# Generated by innovus_enablement/scripts/gen_innovus_lef.py from ../i3dPDK_NS3K/BE/i3dPDK_NS3K_5T_0V7_27C.lef
# Read AFTER the matching i3dPDK_NS3K_<N>T_tech.lef.
VERSION 5.8 ;
BUSBITCHARS "[]" ;
DIVIDERCHAR "/" ;





























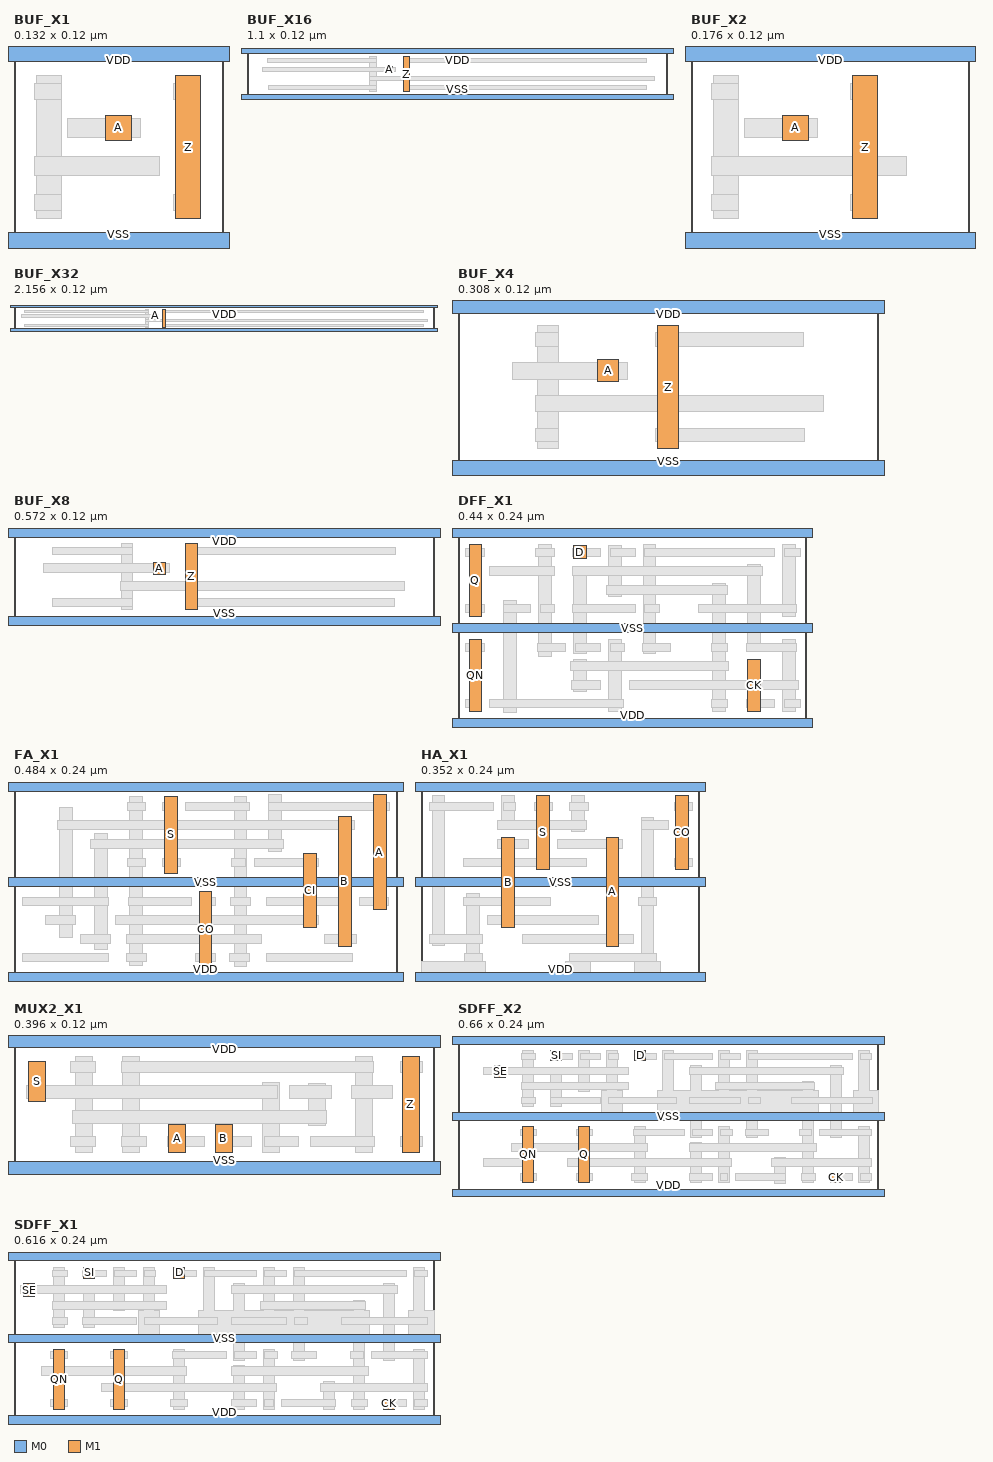
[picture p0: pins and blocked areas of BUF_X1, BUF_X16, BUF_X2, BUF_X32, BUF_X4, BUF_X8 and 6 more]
MACRO BUF_X1
  CLASS CORE ;
  ORIGIN 0 0 ;
  FOREIGN BUF_X1 0 0 ;
  SYMMETRY X Y ;
  SITE i3d_nsfet3nm ;
  SIZE 0.132 BY 0.12 ;
  PIN VDD
    DIRECTION INOUT ;
    USE POWER ;
    PORT
      LAYER M0 ;
        RECT -0.0160 0.1140 0.1480 0.1260 ;
    END
  END VDD
  PIN VSS
    DIRECTION INOUT ;
    USE GROUND ;
    PORT
      LAYER M0 ;
        RECT -0.0160 -0.0060 0.1480 0.0060 ;
    END
  END VSS
  PIN A
    DIRECTION INPUT ;
    USE SIGNAL ;
    PORT
      LAYER M1 ;
        RECT 0.0580 0.0640 0.0740 0.0800 ;
    END
  END A
  PIN Z
    DIRECTION OUTPUT ;
    USE SIGNAL ;
    PORT
      LAYER M1 ;
        RECT 0.1020 0.0150 0.1180 0.1050 ;
    END
  END Z
  OBS
    LAYER M1 DESIGNRULEWIDTH 0 ;
      RECT 0.0140 0.0150 0.0300 0.1050 ;
    LAYER M0 DESIGNRULEWIDTH 0 ;
      RECT 0.1010 0.0200 0.1180 0.0300 ;
      RECT 0.0130 0.0200 0.0300 0.0300 ;
      RECT 0.0130 0.0420 0.0920 0.0540 ;
      RECT 0.0340 0.0660 0.0800 0.0780 ;
      RECT 0.1010 0.0900 0.1180 0.1000 ;
      RECT 0.0130 0.0900 0.0300 0.1000 ;
  END
END BUF_X1

MACRO BUF_X16
  CLASS CORE ;
  ORIGIN 0 0 ;
  FOREIGN BUF_X16 0 0 ;
  SYMMETRY X Y ;
  SITE i3d_nsfet3nm ;
  SIZE 1.1 BY 0.12 ;
  PIN VDD
    DIRECTION INOUT ;
    USE POWER ;
    PORT
      LAYER M0 ;
        RECT -0.0160 0.1140 1.1160 0.1260 ;
    END
  END VDD
  PIN VSS
    DIRECTION INOUT ;
    USE GROUND ;
    PORT
      LAYER M0 ;
        RECT -0.0160 -0.0060 1.1160 0.0060 ;
    END
  END VSS
  PIN A
    DIRECTION INPUT ;
    USE SIGNAL ;
    PORT
      LAYER M1 ;
        RECT 0.3660 0.0640 0.3820 0.0800 ;
    END
  END A
  PIN Z
    DIRECTION OUTPUT ;
    USE SIGNAL ;
    PORT
      LAYER M1 ;
        RECT 0.4100 0.0150 0.4260 0.1050 ;
    END
  END Z
  OBS
    LAYER M1 DESIGNRULEWIDTH 0 ;
      RECT 0.3220 0.0150 0.3380 0.1050 ;
    LAYER M0 DESIGNRULEWIDTH 0 ;
      RECT 0.4090 0.0200 1.0460 0.0300 ;
      RECT 0.0560 0.0200 0.3380 0.0300 ;
      RECT 0.3210 0.0420 1.0660 0.0540 ;
      RECT 0.0400 0.0660 0.3880 0.0780 ;
      RECT 0.4090 0.0900 1.0470 0.1000 ;
      RECT 0.0530 0.0900 0.3380 0.1000 ;
  END
END BUF_X16

MACRO BUF_X2
  CLASS CORE ;
  ORIGIN 0 0 ;
  FOREIGN BUF_X2 0 0 ;
  SYMMETRY X Y ;
  SITE i3d_nsfet3nm ;
  SIZE 0.176 BY 0.12 ;
  PIN VDD
    DIRECTION INOUT ;
    USE POWER ;
    PORT
      LAYER M0 ;
        RECT -0.0160 0.1140 0.1920 0.1260 ;
    END
  END VDD
  PIN VSS
    DIRECTION INOUT ;
    USE GROUND ;
    PORT
      LAYER M0 ;
        RECT -0.0160 -0.0060 0.1920 0.0060 ;
    END
  END VSS
  PIN A
    DIRECTION INPUT ;
    USE SIGNAL ;
    PORT
      LAYER M1 ;
        RECT 0.0580 0.0640 0.0740 0.0800 ;
    END
  END A
  PIN Z
    DIRECTION OUTPUT ;
    USE SIGNAL ;
    PORT
      LAYER M1 ;
        RECT 0.1020 0.0150 0.1180 0.1050 ;
    END
  END Z
  OBS
    LAYER M1 DESIGNRULEWIDTH 0 ;
      RECT 0.0140 0.0150 0.0300 0.1050 ;
    LAYER M0 DESIGNRULEWIDTH 0 ;
      RECT 0.1010 0.0200 0.1180 0.0300 ;
      RECT 0.0130 0.0200 0.0300 0.0300 ;
      RECT 0.0130 0.0420 0.1360 0.0540 ;
      RECT 0.0340 0.0660 0.0800 0.0780 ;
      RECT 0.1010 0.0900 0.1180 0.1000 ;
      RECT 0.0130 0.0900 0.0300 0.1000 ;
  END
END BUF_X2

MACRO BUF_X32
  CLASS CORE ;
  ORIGIN 0 0 ;
  FOREIGN BUF_X32 0 0 ;
  SYMMETRY X Y ;
  SITE i3d_nsfet3nm ;
  SIZE 2.156 BY 0.12 ;
  PIN VDD
    DIRECTION INOUT ;
    USE POWER ;
    PORT
      LAYER M0 ;
        RECT -0.0160 0.1140 2.1720 0.1260 ;
    END
  END VDD
  PIN VSS
    DIRECTION INOUT ;
    USE GROUND ;
    PORT
      LAYER M0 ;
        RECT -0.0160 -0.0060 2.1720 0.0060 ;
    END
  END VSS
  PIN Z
    DIRECTION OUTPUT ;
    USE SIGNAL ;
    PORT
      LAYER M1 ;
        RECT 0.7620 0.0150 0.7780 0.1050 ;
    END
  END Z
  PIN A
    DIRECTION INPUT ;
    USE SIGNAL ;
    PORT
      LAYER M1 ;
        RECT 0.7180 0.0640 0.7340 0.0800 ;
    END
  END A
  OBS
    LAYER M1 DESIGNRULEWIDTH 0 ;
      RECT 0.6740 0.0150 0.6900 0.1050 ;
    LAYER M0 DESIGNRULEWIDTH 0 ;
      RECT 0.7610 0.0200 2.1040 0.0300 ;
      RECT 0.0550 0.0200 0.6900 0.0300 ;
      RECT 0.6730 0.0420 2.1230 0.0540 ;
      RECT 0.0390 0.0660 0.7400 0.0780 ;
      RECT 0.7610 0.0900 2.1010 0.1000 ;
      RECT 0.0530 0.0900 0.6900 0.1000 ;
  END
END BUF_X32

MACRO BUF_X4
  CLASS CORE ;
  ORIGIN 0 0 ;
  FOREIGN BUF_X4 0 0 ;
  SYMMETRY X Y ;
  SITE i3d_nsfet3nm ;
  SIZE 0.308 BY 0.12 ;
  PIN VDD
    DIRECTION INOUT ;
    USE POWER ;
    PORT
      LAYER M0 ;
        RECT -0.0160 0.1140 0.3240 0.1260 ;
    END
  END VDD
  PIN VSS
    DIRECTION INOUT ;
    USE GROUND ;
    PORT
      LAYER M0 ;
        RECT -0.0160 -0.0060 0.3240 0.0060 ;
    END
  END VSS
  PIN A
    DIRECTION INPUT ;
    USE SIGNAL ;
    PORT
      LAYER M1 ;
        RECT 0.1020 0.0640 0.1180 0.0800 ;
    END
  END A
  PIN Z
    DIRECTION OUTPUT ;
    USE SIGNAL ;
    PORT
      LAYER M1 ;
        RECT 0.1460 0.0150 0.1620 0.1050 ;
    END
  END Z
  OBS
    LAYER M1 DESIGNRULEWIDTH 0 ;
      RECT 0.0580 0.0150 0.0740 0.1050 ;
    LAYER M0 DESIGNRULEWIDTH 0 ;
      RECT 0.1450 0.0200 0.2540 0.0300 ;
      RECT 0.0570 0.0200 0.0740 0.0300 ;
      RECT 0.0570 0.0420 0.2680 0.0540 ;
      RECT 0.0400 0.0660 0.1240 0.0780 ;
      RECT 0.1450 0.0900 0.2530 0.1000 ;
      RECT 0.0570 0.0900 0.0740 0.1000 ;
  END
END BUF_X4

MACRO BUF_X8
  CLASS CORE ;
  ORIGIN 0 0 ;
  FOREIGN BUF_X8 0 0 ;
  SYMMETRY X Y ;
  SITE i3d_nsfet3nm ;
  SIZE 0.572 BY 0.12 ;
  PIN VDD
    DIRECTION INOUT ;
    USE POWER ;
    PORT
      LAYER M0 ;
        RECT -0.0160 0.1140 0.5880 0.1260 ;
    END
  END VDD
  PIN VSS
    DIRECTION INOUT ;
    USE GROUND ;
    PORT
      LAYER M0 ;
        RECT -0.0160 -0.0060 0.5880 0.0060 ;
    END
  END VSS
  PIN A
    DIRECTION INPUT ;
    USE SIGNAL ;
    PORT
      LAYER M1 ;
        RECT 0.1900 0.0640 0.2060 0.0800 ;
    END
  END A
  PIN Z
    DIRECTION OUTPUT ;
    USE SIGNAL ;
    PORT
      LAYER M1 ;
        RECT 0.2340 0.0150 0.2500 0.1050 ;
    END
  END Z
  OBS
    LAYER M1 DESIGNRULEWIDTH 0 ;
      RECT 0.1460 0.0150 0.1620 0.1050 ;
    LAYER M0 DESIGNRULEWIDTH 0 ;
      RECT 0.2330 0.0200 0.5180 0.0300 ;
      RECT 0.0520 0.0200 0.1620 0.0300 ;
      RECT 0.1450 0.0420 0.5320 0.0540 ;
      RECT 0.0400 0.0660 0.2120 0.0780 ;
      RECT 0.2330 0.0900 0.5190 0.1000 ;
      RECT 0.0520 0.0900 0.1620 0.1000 ;
  END
END BUF_X8

MACRO DFF_X1
  CLASS CORE ;
  ORIGIN 0 0 ;
  FOREIGN DFF_X1 0 0 ;
  SYMMETRY X Y ;
  SITE i3d_nsfet3nm_2H_VDD ;
  SIZE 0.44 BY 0.24 ;
  PIN Q
    DIRECTION OUTPUT ;
    USE SIGNAL ;
    PORT
      LAYER M1 ;
        RECT 0.0140 0.1350 0.0300 0.2250 ;
    END
  END Q
  PIN VDD
    DIRECTION INOUT ;
    USE POWER ;
    PORT
      LAYER M0 ;
        RECT -0.0160 0.2340 0.4560 0.2460 ;
        RECT -0.0160 -0.0060 0.4560 0.0060 ;
    END
  END VDD
  PIN VSS
    DIRECTION INOUT ;
    USE GROUND ;
    PORT
      LAYER M0 ;
        RECT -0.0160 0.1140 0.4560 0.1260 ;
    END
  END VSS
  PIN D
    DIRECTION INPUT ;
    USE SIGNAL ;
    PORT
      LAYER M1 ;
        RECT 0.1460 0.2080 0.1620 0.2240 ;
    END
  END D
  PIN QN
    DIRECTION OUTPUT ;
    USE SIGNAL ;
    PORT
      LAYER M1 ;
        RECT 0.0140 0.0150 0.0300 0.1050 ;
    END
  END QN
  PIN CK
    DIRECTION INPUT ;
    USE SIGNAL ;
    PORT
      LAYER M1 ;
        RECT 0.3660 0.0150 0.3820 0.0800 ;
    END
  END CK
  OBS
    LAYER M1 ;
      RECT 0.0580 0.0130 0.0740 0.1550 ;
      RECT 0.1900 0.0150 0.2060 0.1050 ;
      RECT 0.3220 0.0150 0.3380 0.1760 ;
      RECT 0.4100 0.0150 0.4260 0.1050 ;
      RECT 0.1460 0.0400 0.1620 0.0800 ;
      RECT 0.1020 0.0840 0.1180 0.2250 ;
      RECT 0.1460 0.0880 0.1620 0.1880 ;
      RECT 0.2340 0.0880 0.2500 0.2250 ;
      RECT 0.3660 0.1000 0.3820 0.2000 ;
      RECT 0.4100 0.1350 0.4260 0.2250 ;
      RECT 0.1900 0.1600 0.2060 0.2240 ;
    LAYER M0 ;
      RECT 0.0100 0.0200 0.0280 0.0300 ;
      RECT 0.0400 0.0200 0.2090 0.0300 ;
      RECT 0.3200 0.0200 0.3400 0.0300 ;
      RECT 0.3650 0.0200 0.4000 0.0300 ;
      RECT 0.4120 0.0200 0.4320 0.0300 ;
      RECT 0.1430 0.0420 0.1800 0.0540 ;
      RECT 0.2160 0.0420 0.4300 0.0540 ;
      RECT 0.1420 0.0660 0.3420 0.0780 ;
      RECT 0.0100 0.0900 0.0340 0.1000 ;
      RECT 0.1000 0.0900 0.1360 0.1000 ;
      RECT 0.1480 0.0900 0.1800 0.1000 ;
      RECT 0.1920 0.0900 0.2100 0.1000 ;
      RECT 0.2330 0.0900 0.2680 0.1000 ;
      RECT 0.3200 0.0900 0.3400 0.1000 ;
      RECT 0.3640 0.0900 0.4280 0.1000 ;
      RECT 0.0100 0.1400 0.0340 0.1500 ;
      RECT 0.0570 0.1400 0.0920 0.1500 ;
      RECT 0.1040 0.1400 0.1220 0.1500 ;
      RECT 0.1440 0.1400 0.2240 0.1500 ;
      RECT 0.2360 0.1400 0.2550 0.1500 ;
      RECT 0.3040 0.1400 0.4280 0.1500 ;
      RECT 0.1870 0.1620 0.3400 0.1740 ;
      RECT 0.0400 0.1860 0.1220 0.1980 ;
      RECT 0.1450 0.1860 0.3840 0.1980 ;
      RECT 0.0100 0.2100 0.0340 0.2200 ;
      RECT 0.0980 0.2100 0.1220 0.2200 ;
      RECT 0.1440 0.2100 0.1800 0.2200 ;
      RECT 0.1920 0.2100 0.2240 0.2200 ;
      RECT 0.2360 0.2100 0.4000 0.2200 ;
      RECT 0.4120 0.2100 0.4320 0.2200 ;
  END
END DFF_X1


MACRO FA_X1
  CLASS CORE ;
  ORIGIN 0 0 ;
  FOREIGN FA 0 0 ;
  SYMMETRY X Y ;
  SITE i3d_nsfet3nm_2H_VDD ;
  SIZE 0.484 BY 0.24 ;
  PIN VDD
    DIRECTION INOUT ;
    USE POWER ;
    PORT
      LAYER M0 ;
        RECT -0.0160 -0.0060 0.5000 0.0060 ;
        RECT -0.0160 0.2340 0.5000 0.2460 ;
    END
  END VDD
  PIN VSS
    DIRECTION INOUT ;
    USE GROUND ;
    PORT
      LAYER M0 ;
        RECT -0.0160 0.1140 0.5000 0.1260 ;
    END
  END VSS
  PIN CO
    DIRECTION OUTPUT ;
    USE SIGNAL ;
    PORT
      LAYER M1 ;
        RECT 0.2340 0.0130 0.2500 0.1080 ;
    END
  END CO
  PIN CI
    DIRECTION INPUT ;
    USE SIGNAL ;
    PORT
      LAYER M1 ;
        RECT 0.3660 0.0630 0.3820 0.1560 ;
    END
  END CI
  PIN A
    DIRECTION INPUT ;
    USE SIGNAL ;
    PORT
      LAYER M1 ;
        RECT 0.4540 0.0850 0.4700 0.2300 ;
    END
  END A
  PIN B
    DIRECTION INPUT ;
    USE SIGNAL ;
    PORT
      LAYER M1 ;
        RECT 0.4100 0.0390 0.4260 0.2030 ;
    END
  END B
  PIN S
    DIRECTION OUTPUT ;
    USE SIGNAL ;
    PORT
      LAYER M1 ;
        RECT 0.1900 0.1310 0.2060 0.2280 ;
    END
  END S
  OBS
    LAYER M1 DESIGNRULEWIDTH 0 ;
      RECT 0.2780 0.0130 0.2940 0.2280 ;
      RECT 0.1460 0.0140 0.1620 0.2280 ;
      RECT 0.1020 0.0350 0.1180 0.1810 ;
      RECT 0.0580 0.0500 0.0740 0.2140 ;
      RECT 0.3220 0.1590 0.3380 0.2300 ;
    LAYER M0 DESIGNRULEWIDTH 0 ;
      RECT 0.3190 0.0200 0.4270 0.0300 ;
      RECT 0.2720 0.0200 0.2970 0.0300 ;
      RECT 0.2290 0.0200 0.2540 0.0300 ;
      RECT 0.1420 0.0200 0.1670 0.0300 ;
      RECT 0.0110 0.0200 0.1190 0.0300 ;
      RECT 0.3920 0.0420 0.4320 0.0540 ;
      RECT 0.1420 0.0420 0.3120 0.0540 ;
      RECT 0.0840 0.0420 0.1220 0.0540 ;
      RECT 0.1280 0.0660 0.3840 0.0780 ;
      RECT 0.0400 0.0660 0.0780 0.0780 ;
      RECT 0.4360 0.0900 0.4730 0.1000 ;
      RECT 0.3190 0.0900 0.4240 0.1000 ;
      RECT 0.2740 0.0900 0.2990 0.1000 ;
      RECT 0.2360 0.0900 0.2540 0.1000 ;
      RECT 0.1440 0.0900 0.2240 0.1000 ;
      RECT 0.0110 0.0900 0.1190 0.1000 ;
      RECT 0.3040 0.1400 0.3840 0.1500 ;
      RECT 0.2750 0.1400 0.2920 0.1500 ;
      RECT 0.1870 0.1400 0.2100 0.1500 ;
      RECT 0.1430 0.1400 0.1660 0.1500 ;
      RECT 0.0970 0.1620 0.3400 0.1740 ;
      RECT 0.0550 0.1860 0.4300 0.1980 ;
      RECT 0.3210 0.2100 0.4740 0.2200 ;
      RECT 0.2160 0.2100 0.2980 0.2200 ;
      RECT 0.1870 0.2100 0.2040 0.2200 ;
      RECT 0.1430 0.2100 0.1660 0.2200 ;
  END
END FA_X1

MACRO HA_X1
  CLASS CORE ;
  ORIGIN 0 0 ;
  FOREIGN HA 0 0 ;
  SYMMETRY X Y ;
  SITE i3d_nsfet3nm_2H_VDD ;
  SIZE 0.352 BY 0.24 ;
  PIN VDD
    DIRECTION INOUT ;
    USE POWER ;
    PORT
      LAYER M0 ;
        RECT -0.0160 -0.0060 0.3680 0.0060 ;
        RECT -0.0160 0.2340 0.3680 0.2460 ;
    END
  END VDD
  PIN S
    DIRECTION OUTPUT ;
    USE SIGNAL ;
    PORT
      LAYER M1 ;
        RECT 0.1460 0.1360 0.1620 0.2290 ;
    END
  END S
  PIN B
    DIRECTION INPUT ;
    USE SIGNAL ;
    PORT
      LAYER M1 ;
        RECT 0.1020 0.0630 0.1180 0.1760 ;
    END
  END B
  PIN A
    DIRECTION INPUT ;
    USE SIGNAL ;
    PORT
      LAYER M1 ;
        RECT 0.2340 0.0390 0.2500 0.1760 ;
    END
  END A
  PIN VSS
    DIRECTION INOUT ;
    USE GROUND ;
    PORT
      LAYER M0 ;
        RECT -0.0160 0.1140 0.3680 0.1260 ;
    END
  END VSS
  PIN CO
    DIRECTION OUTPUT ;
    USE SIGNAL ;
    PORT
      LAYER M1 ;
        RECT 0.3220 0.1360 0.3380 0.2290 ;
    END
  END CO
  OBS
    LAYER M1 DESIGNRULEWIDTH 0 ;
      POLYGON 0.3020 0.0000 0.3020 0.0190 0.2940 0.0190 0.2940 0.2010 0.2780 0.2010 0.2780 0.0190 0.2700 0.0190 0.2700 0.0000 ;
      RECT 0.1820 0.0000 0.2140 0.0190 ;
      POLYGON 0.0820 0.0000 0.0820 0.0190 0.0740 0.0190 0.0740 0.1050 0.0580 0.1050 0.0580 0.0190 0.0000 0.0190 0.0000 0.0000 ;
      RECT 0.0140 0.0400 0.0300 0.2290 ;
      RECT 0.1900 0.1840 0.2060 0.2290 ;
      RECT 0.1020 0.1960 0.1180 0.2290 ;
    LAYER M0 DESIGNRULEWIDTH 0 ;
      RECT 0.1870 0.0200 0.2980 0.0300 ;
      RECT 0.0550 0.0200 0.0780 0.0300 ;
      RECT 0.1280 0.0420 0.2680 0.0540 ;
      RECT 0.0110 0.0420 0.0780 0.0540 ;
      RECT 0.0840 0.0660 0.2240 0.0780 ;
      RECT 0.2750 0.0900 0.2980 0.1000 ;
      RECT 0.0540 0.0900 0.1640 0.1000 ;
      RECT 0.3200 0.1400 0.3430 0.1500 ;
      RECT 0.0540 0.1400 0.2090 0.1500 ;
      RECT 0.1720 0.1620 0.2540 0.1740 ;
      RECT 0.0970 0.1620 0.1360 0.1740 ;
      RECT 0.2780 0.1860 0.3120 0.1980 ;
      RECT 0.0970 0.1860 0.2090 0.1980 ;
      RECT 0.3200 0.2100 0.3430 0.2200 ;
      RECT 0.1880 0.2100 0.2110 0.2200 ;
      RECT 0.1430 0.2100 0.1660 0.2200 ;
      RECT 0.1040 0.2100 0.1190 0.2200 ;
      RECT 0.0110 0.2100 0.0920 0.2200 ;
  END
END HA_X1

MACRO MUX2_X1
  CLASS CORE ;
  ORIGIN 0 0 ;
  FOREIGN MUX2_X1 0 0 ;
  SYMMETRY X Y ;
  SITE i3d_nsfet3nm ;
  SIZE 0.396 BY 0.12 ;
  PIN VDD
    DIRECTION INOUT ;
    USE POWER ;
    PORT
      LAYER M0 ;
        RECT -0.0160 0.1140 0.4120 0.1260 ;
    END
  END VDD
  PIN VSS
    DIRECTION INOUT ;
    USE GROUND ;
    PORT
      LAYER M0 ;
        RECT -0.0160 -0.0060 0.4120 0.0060 ;
    END
  END VSS
  PIN A
    DIRECTION INPUT ;
    USE SIGNAL ;
    PORT
      LAYER M1 ;
        RECT 0.1460 0.0150 0.1620 0.0410 ;
    END
  END A
  PIN B
    DIRECTION INPUT ;
    USE SIGNAL ;
    PORT
      LAYER M1 ;
        RECT 0.1900 0.0150 0.2060 0.0410 ;
    END
  END B
  PIN S
    DIRECTION INPUT ;
    USE SIGNAL ;
    PORT
      LAYER M1 ;
        RECT 0.0140 0.0630 0.0300 0.1000 ;
    END
  END S
  PIN Z
    DIRECTION OUTPUT ;
    USE SIGNAL ;
    PORT
      LAYER M1 ;
        RECT 0.3660 0.0150 0.3820 0.1050 ;
    END
  END Z
  OBS
    LAYER M1 DESIGNRULEWIDTH 0 ;
      RECT 0.3220 0.0150 0.3380 0.1050 ;
      RECT 0.2340 0.0150 0.2500 0.0810 ;
      RECT 0.1020 0.0150 0.1180 0.1050 ;
      RECT 0.0580 0.0150 0.0740 0.1050 ;
      RECT 0.2780 0.0400 0.2940 0.0800 ;
    LAYER M0 DESIGNRULEWIDTH 0 ;
      RECT 0.3640 0.0200 0.3850 0.0300 ;
      RECT 0.2800 0.0200 0.3400 0.0300 ;
      RECT 0.2360 0.0200 0.2680 0.0300 ;
      RECT 0.1920 0.0200 0.2240 0.0300 ;
      RECT 0.1450 0.0200 0.1800 0.0300 ;
      RECT 0.1010 0.0200 0.1250 0.0300 ;
      RECT 0.0530 0.0200 0.0770 0.0300 ;
      RECT 0.0550 0.0420 0.2950 0.0540 ;
      RECT 0.3180 0.0660 0.3570 0.0780 ;
      RECT 0.2600 0.0660 0.2990 0.0780 ;
      RECT 0.0120 0.0660 0.2480 0.0780 ;
      RECT 0.3640 0.0900 0.3850 0.1000 ;
      RECT 0.1010 0.0900 0.3390 0.1000 ;
      RECT 0.0530 0.0900 0.0770 0.1000 ;
  END
END MUX2_X1

MACRO SDFF_X2
  CLASS CORE ;
  ORIGIN 0 0 ;
  FOREIGN SDFF_X2 0 0 ;
  SYMMETRY X Y ;
  SITE i3d_nsfet3nm_2H_VDD ;
  SIZE 0.66 BY 0.24 ;
  PIN VDD
    DIRECTION INOUT ;
    USE POWER ;
    PORT
      LAYER M0 ;
        RECT -0.0160 -0.0060 0.6760 0.0060 ;
        RECT -0.0160 0.2340 0.6760 0.2460 ;
    END
  END VDD
  PIN VSS
    DIRECTION INOUT ;
    USE GROUND ;
    PORT
      LAYER M0 ;
        RECT -0.0160 0.1140 0.6760 0.1260 ;
    END
  END VSS
  PIN Q
    DIRECTION OUTPUT ;
    USE SIGNAL ;
    PORT
      LAYER M1 ;
        RECT 0.1900 0.0160 0.2060 0.1040 ;
    END
  END Q
  PIN QN
    DIRECTION OUTPUT ;
    USE SIGNAL ;
    PORT
      LAYER M1 ;
        RECT 0.1020 0.0160 0.1180 0.1040 ;
    END
  END QN
  PIN SE
    DIRECTION INPUT ;
    USE SIGNAL ;
    PORT
      LAYER M1 ;
        RECT 0.0580 0.1810 0.0740 0.2000 ;
    END
  END SE
  PIN SI
    DIRECTION INPUT ;
    USE SIGNAL ;
    PORT
      LAYER M1 ;
        RECT 0.1460 0.2080 0.1620 0.2240 ;
    END
  END SI
  PIN D
    DIRECTION INPUT ;
    USE SIGNAL ;
    PORT
      LAYER M1 ;
        RECT 0.2780 0.2080 0.2940 0.2240 ;
    END
  END D
  PIN CK
    DIRECTION INPUT ;
    USE SIGNAL ;
    PORT
      LAYER M1 ;
        RECT 0.5860 0.0160 0.6020 0.0320 ;
    END
  END CK
  OBS
    LAYER M1 DESIGNRULEWIDTH 0 ;
      RECT 0.4980 0.0150 0.5140 0.0560 ;
      RECT 0.2780 0.0160 0.2940 0.1040 ;
      RECT 0.3660 0.0160 0.3820 0.0800 ;
      RECT 0.4100 0.0160 0.4260 0.1040 ;
      POLYGON 0.5580 0.0160 0.5580 0.1240 0.5660 0.1240 0.5660 0.1610 0.5580 0.1610 0.5580 0.1760 0.5420 0.1760 0.5420 0.1610 0.4700 0.1610 0.4700 0.2240 0.4540 0.2240 0.4540 0.1610 0.4260 0.1610 0.4260 0.2240 0.4100 0.2240 0.4100 0.1610 0.3820 0.1610 0.3820 0.2000 0.3660 0.2000 0.3660 0.1610 0.3380 0.1610 0.3380 0.2240 0.3220 0.2240 0.3220 0.1610 0.3140 0.1610 0.3140 0.1240 0.3660 0.1240 0.3660 0.0880 0.3820 0.0880 0.3820 0.1240 0.4540 0.1240 0.4540 0.0880 0.4700 0.0880 0.4700 0.1240 0.5420 0.1240 0.5420 0.0160 ;
      RECT 0.6300 0.0160 0.6460 0.1040 ;
      RECT 0.5860 0.0880 0.6020 0.2000 ;
      POLYGON 0.2580 0.1240 0.2580 0.1610 0.2500 0.1610 0.2500 0.2240 0.2340 0.2240 0.2340 0.1610 0.2260 0.1610 0.2260 0.1240 ;
      POLYGON 0.6600 0.1240 0.6600 0.1610 0.6460 0.1610 0.6460 0.2240 0.6300 0.2240 0.6300 0.1610 0.6220 0.1610 0.6220 0.1240 ;
      RECT 0.1020 0.1360 0.1180 0.2240 ;
      RECT 0.1460 0.1360 0.1620 0.1880 ;
      RECT 0.1900 0.1600 0.2060 0.2240 ;
    LAYER M0 DESIGNRULEWIDTH 0 ;
      RECT 0.0980 0.0200 0.1230 0.0300 ;
      RECT 0.1860 0.0200 0.2110 0.0300 ;
      RECT 0.2730 0.0200 0.2980 0.0300 ;
      RECT 0.3630 0.0200 0.4000 0.0300 ;
      RECT 0.4120 0.0200 0.4240 0.0300 ;
      RECT 0.4360 0.0200 0.5150 0.0300 ;
      RECT 0.5390 0.0200 0.5620 0.0300 ;
      RECT 0.5830 0.0200 0.6200 0.0300 ;
      RECT 0.6320 0.0200 0.6500 0.0300 ;
      RECT 0.0400 0.0420 0.1060 0.0540 ;
      RECT 0.1720 0.0420 0.4290 0.0540 ;
      RECT 0.4930 0.0420 0.6500 0.0540 ;
      RECT 0.0840 0.0660 0.2970 0.0780 ;
      RECT 0.3630 0.0660 0.5640 0.0780 ;
      RECT 0.0980 0.0900 0.1230 0.1000 ;
      RECT 0.1860 0.0900 0.2110 0.1000 ;
      RECT 0.2760 0.0900 0.3560 0.1000 ;
      RECT 0.3680 0.0900 0.4000 0.1000 ;
      RECT 0.4120 0.0900 0.4310 0.1000 ;
      RECT 0.4510 0.0900 0.4880 0.1000 ;
      RECT 0.5370 0.0900 0.5560 0.1000 ;
      RECT 0.5680 0.0900 0.6500 0.1000 ;
      RECT 0.1000 0.1400 0.1220 0.1500 ;
      RECT 0.1450 0.1400 0.2240 0.1500 ;
      RECT 0.2360 0.1400 0.3430 0.1500 ;
      RECT 0.3630 0.1400 0.4440 0.1500 ;
      RECT 0.4560 0.1400 0.4750 0.1500 ;
      RECT 0.5240 0.1400 0.6510 0.1500 ;
      RECT 0.1000 0.1620 0.2680 0.1740 ;
      RECT 0.4050 0.1620 0.5600 0.1740 ;
      RECT 0.0400 0.1860 0.2680 0.1980 ;
      RECT 0.3630 0.1860 0.6060 0.1980 ;
      RECT 0.1000 0.2100 0.1220 0.2200 ;
      RECT 0.1450 0.2100 0.1800 0.2200 ;
      RECT 0.1920 0.2100 0.2240 0.2200 ;
      RECT 0.2360 0.2100 0.2520 0.2200 ;
      RECT 0.2800 0.2100 0.3120 0.2200 ;
      RECT 0.3240 0.2100 0.4000 0.2200 ;
      RECT 0.4120 0.2100 0.4440 0.2200 ;
      RECT 0.4560 0.2100 0.6200 0.2200 ;
      RECT 0.6320 0.2100 0.6500 0.2200 ;
  END
END SDFF_X2

MACRO SDFF_X1
  CLASS CORE ;
  ORIGIN 0 0 ;
  FOREIGN SDFF_X1 0 0 ;
  SYMMETRY X Y ;
  SITE i3d_nsfet3nm_2H_VDD ;
  SIZE 0.616 BY 0.24 ;
  PIN VDD
    DIRECTION INOUT ;
    USE POWER ;
    PORT
      LAYER M0 ;
        RECT -0.0160 -0.0060 0.6320 0.0060 ;
        RECT -0.0160 0.2340 0.6320 0.2460 ;
    END
  END VDD
  PIN VSS
    DIRECTION INOUT ;
    USE GROUND ;
    PORT
      LAYER M0 ;
        RECT -0.0160 0.1140 0.6320 0.1260 ;
    END
  END VSS
  PIN Q
    DIRECTION OUTPUT ;
    USE SIGNAL ;
    PORT
      LAYER M1 ;
        RECT 0.1460 0.0160 0.1620 0.1040 ;
    END
  END Q
  PIN QN
    DIRECTION OUTPUT ;
    USE SIGNAL ;
    PORT
      LAYER M1 ;
        RECT 0.0580 0.0160 0.0740 0.1040 ;
    END
  END QN
  PIN SE
    DIRECTION INPUT ;
    USE SIGNAL ;
    PORT
      LAYER M1 ;
        RECT 0.0140 0.1810 0.0300 0.2000 ;
    END
  END SE
  PIN SI
    DIRECTION INPUT ;
    USE SIGNAL ;
    PORT
      LAYER M1 ;
        RECT 0.1020 0.2080 0.1180 0.2240 ;
    END
  END SI
  PIN D
    DIRECTION INPUT ;
    USE SIGNAL ;
    PORT
      LAYER M1 ;
        RECT 0.2340 0.2080 0.2500 0.2240 ;
    END
  END D
  PIN CK
    DIRECTION INPUT ;
    USE SIGNAL ;
    PORT
      LAYER M1 ;
        RECT 0.5420 0.0160 0.5580 0.0320 ;
    END
  END CK
  OBS
    LAYER M1 DESIGNRULEWIDTH 0 ;
      RECT 0.4540 0.0150 0.4700 0.0560 ;
      RECT 0.5860 0.0160 0.6020 0.1040 ;
      POLYGON 0.5140 0.0160 0.5140 0.1240 0.5220 0.1240 0.5220 0.1610 0.5140 0.1610 0.5140 0.1760 0.4980 0.1760 0.4980 0.1610 0.4260 0.1610 0.4260 0.2240 0.4100 0.2240 0.4100 0.1610 0.3820 0.1610 0.3820 0.2240 0.3660 0.2240 0.3660 0.1610 0.3380 0.1610 0.3380 0.2000 0.3220 0.2000 0.3220 0.1610 0.2940 0.1610 0.2940 0.2240 0.2780 0.2240 0.2780 0.1610 0.2700 0.1610 0.2700 0.1240 0.3220 0.1240 0.3220 0.0880 0.3380 0.0880 0.3380 0.1240 0.4100 0.1240 0.4100 0.0880 0.4260 0.0880 0.4260 0.1240 0.4980 0.1240 0.4980 0.0160 ;
      RECT 0.3660 0.0160 0.3820 0.1040 ;
      RECT 0.3220 0.0160 0.3380 0.0800 ;
      RECT 0.2340 0.0160 0.2500 0.1040 ;
      RECT 0.5420 0.0880 0.5580 0.2000 ;
      POLYGON 0.6160 0.1240 0.6160 0.1610 0.6020 0.1610 0.6020 0.2240 0.5860 0.2240 0.5860 0.1610 0.5780 0.1610 0.5780 0.1240 ;
      POLYGON 0.2140 0.1240 0.2140 0.1610 0.2060 0.1610 0.2060 0.2240 0.1900 0.2240 0.1900 0.1610 0.1820 0.1610 0.1820 0.1240 ;
      RECT 0.1020 0.1360 0.1180 0.1880 ;
      RECT 0.0580 0.1360 0.0740 0.2240 ;
      RECT 0.1460 0.1600 0.1620 0.2240 ;
    LAYER M0 DESIGNRULEWIDTH 0 ;
      RECT 0.5880 0.0200 0.6060 0.0300 ;
      RECT 0.5390 0.0200 0.5760 0.0300 ;
      RECT 0.4950 0.0200 0.5180 0.0300 ;
      RECT 0.3920 0.0200 0.4710 0.0300 ;
      RECT 0.3680 0.0200 0.3800 0.0300 ;
      RECT 0.3190 0.0200 0.3560 0.0300 ;
      RECT 0.2290 0.0200 0.2540 0.0300 ;
      RECT 0.1420 0.0200 0.1670 0.0300 ;
      RECT 0.0540 0.0200 0.0790 0.0300 ;
      RECT 0.4490 0.0420 0.6060 0.0540 ;
      RECT 0.1280 0.0420 0.3850 0.0540 ;
      RECT 0.3190 0.0660 0.5200 0.0780 ;
      RECT 0.0400 0.0660 0.2530 0.0780 ;
      RECT 0.5240 0.0900 0.6060 0.1000 ;
      RECT 0.4930 0.0900 0.5120 0.1000 ;
      RECT 0.4070 0.0900 0.4440 0.1000 ;
      RECT 0.3680 0.0900 0.3870 0.1000 ;
      RECT 0.3240 0.0900 0.3560 0.1000 ;
      RECT 0.2320 0.0900 0.3120 0.1000 ;
      RECT 0.1420 0.0900 0.1670 0.1000 ;
      RECT 0.0540 0.0900 0.0790 0.1000 ;
      RECT 0.4800 0.1400 0.6070 0.1500 ;
      RECT 0.4120 0.1400 0.4310 0.1500 ;
      RECT 0.3190 0.1400 0.4000 0.1500 ;
      RECT 0.1920 0.1400 0.2990 0.1500 ;
      RECT 0.1010 0.1400 0.1800 0.1500 ;
      RECT 0.0560 0.1400 0.0780 0.1500 ;
      RECT 0.3610 0.1620 0.5160 0.1740 ;
      RECT 0.0560 0.1620 0.2240 0.1740 ;
      RECT 0.3190 0.1860 0.5620 0.1980 ;
      RECT 0.0100 0.1860 0.2240 0.1980 ;
      RECT 0.5880 0.2100 0.6060 0.2200 ;
      RECT 0.4120 0.2100 0.5760 0.2200 ;
      RECT 0.3680 0.2100 0.4000 0.2200 ;
      RECT 0.2800 0.2100 0.3560 0.2200 ;
      RECT 0.2360 0.2100 0.2680 0.2200 ;
      RECT 0.1920 0.2100 0.2080 0.2200 ;
      RECT 0.1480 0.2100 0.1800 0.2200 ;
      RECT 0.1010 0.2100 0.1360 0.2200 ;
      RECT 0.0560 0.2100 0.0780 0.2200 ;
  END
END SDFF_X1

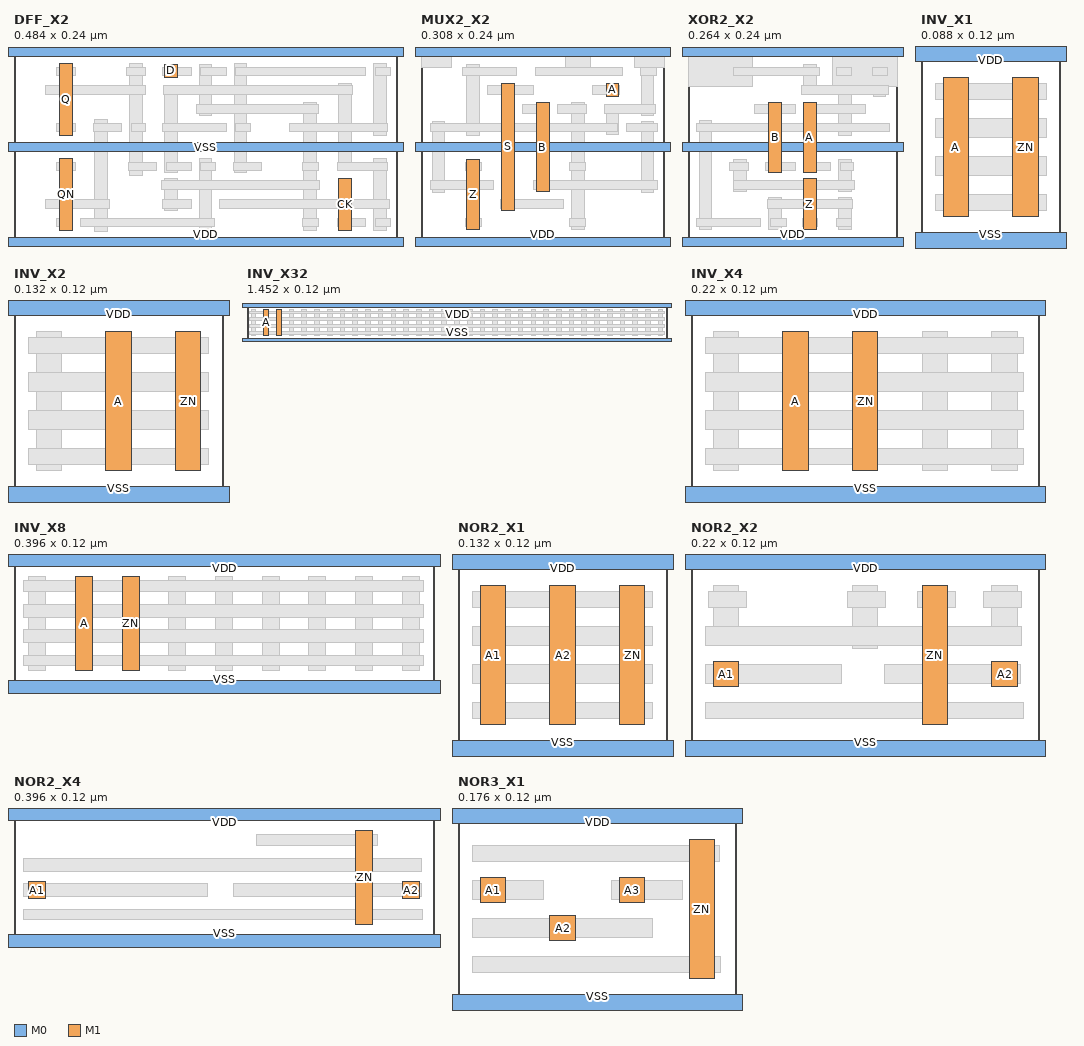
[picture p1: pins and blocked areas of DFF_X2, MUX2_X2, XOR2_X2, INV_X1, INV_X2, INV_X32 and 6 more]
MACRO DFF_X2
  CLASS CORE ;
  ORIGIN 0 0 ;
  FOREIGN DFF_X2 0 0 ;
  SYMMETRY X Y ;
  SITE i3d_nsfet3nm_2H_VDD ;
  SIZE 0.484 BY 0.24 ;
  PIN VDD
    DIRECTION INOUT ;
    USE POWER ;
    PORT
      LAYER M0 ;
        RECT -0.0160 -0.0060 0.5000 0.0060 ;
        RECT -0.0160 0.2340 0.5000 0.2460 ;
    END
  END VDD
  PIN VSS
    DIRECTION INOUT ;
    USE GROUND ;
    PORT
      LAYER M0 ;
        RECT -0.0160 0.1140 0.5000 0.1260 ;
    END
  END VSS
  PIN QN
    DIRECTION OUTPUT ;
    USE SIGNAL ;
    PORT
      LAYER M1 ;
        RECT 0.0580 0.0150 0.0740 0.1050 ;
    END
  END QN
  PIN Q
    DIRECTION OUTPUT ;
    USE SIGNAL ;
    PORT
      LAYER M1 ;
        RECT 0.0580 0.1350 0.0740 0.2250 ;
    END
  END Q
  PIN CK
    DIRECTION INPUT ;
    USE SIGNAL ;
    PORT
      LAYER M1 ;
        RECT 0.4100 0.0150 0.4260 0.0800 ;
    END
  END CK
  PIN D
    DIRECTION INPUT ;
    USE SIGNAL ;
    PORT
      LAYER M1 ;
        RECT 0.1900 0.2080 0.2060 0.2240 ;
    END
  END D
  OBS
    LAYER M1 DESIGNRULEWIDTH 0 ;
      RECT 0.1020 0.0130 0.1180 0.1550 ;
      RECT 0.4540 0.0150 0.4700 0.1050 ;
      RECT 0.3660 0.0150 0.3820 0.1760 ;
      RECT 0.2340 0.0150 0.2500 0.1050 ;
      RECT 0.1900 0.0400 0.2060 0.0800 ;
      RECT 0.1460 0.0840 0.1620 0.2250 ;
      RECT 0.2780 0.0880 0.2940 0.2250 ;
      RECT 0.1900 0.0880 0.2060 0.1880 ;
      RECT 0.4100 0.1000 0.4260 0.2000 ;
      RECT 0.4540 0.1350 0.4700 0.2250 ;
      RECT 0.2340 0.1600 0.2500 0.2240 ;
    LAYER M0 DESIGNRULEWIDTH 0 ;
      RECT 0.4560 0.0200 0.4760 0.0300 ;
      RECT 0.4090 0.0200 0.4440 0.0300 ;
      RECT 0.3640 0.0200 0.3840 0.0300 ;
      RECT 0.0840 0.0200 0.2530 0.0300 ;
      RECT 0.0540 0.0200 0.0720 0.0300 ;
      RECT 0.2600 0.0420 0.4740 0.0540 ;
      RECT 0.1870 0.0420 0.2240 0.0540 ;
      RECT 0.0400 0.0420 0.1210 0.0540 ;
      RECT 0.1860 0.0660 0.3860 0.0780 ;
      RECT 0.4080 0.0900 0.4720 0.1000 ;
      RECT 0.3640 0.0900 0.3840 0.1000 ;
      RECT 0.2770 0.0900 0.3120 0.1000 ;
      RECT 0.2360 0.0900 0.2540 0.1000 ;
      RECT 0.1920 0.0900 0.2240 0.1000 ;
      RECT 0.1440 0.0900 0.1800 0.1000 ;
      RECT 0.0540 0.0900 0.0780 0.1000 ;
      RECT 0.3480 0.1400 0.4720 0.1500 ;
      RECT 0.2800 0.1400 0.2990 0.1500 ;
      RECT 0.1880 0.1400 0.2680 0.1500 ;
      RECT 0.1480 0.1400 0.1660 0.1500 ;
      RECT 0.1010 0.1400 0.1360 0.1500 ;
      RECT 0.0540 0.1400 0.0780 0.1500 ;
      RECT 0.2310 0.1620 0.3840 0.1740 ;
      RECT 0.1890 0.1860 0.4280 0.1980 ;
      RECT 0.0400 0.1860 0.1660 0.1980 ;
      RECT 0.4560 0.2100 0.4760 0.2200 ;
      RECT 0.2800 0.2100 0.4440 0.2200 ;
      RECT 0.2360 0.2100 0.2680 0.2200 ;
      RECT 0.1880 0.2100 0.2240 0.2200 ;
      RECT 0.1420 0.2100 0.1660 0.2200 ;
      RECT 0.0540 0.2100 0.0780 0.2200 ;
  END
END DFF_X2

MACRO MUX2_X2
  CLASS CORE ;
  ORIGIN 0 0 ;
  FOREIGN MUX2_X2 0 0 ;
  SYMMETRY X Y ;
  SITE i3d_nsfet3nm_2H_VDD ;
  SIZE 0.308 BY 0.24 ;
  PIN VDD
    DIRECTION INOUT ;
    USE POWER ;
    PORT
      LAYER M0 ;
        RECT -0.0160 -0.0060 0.3240 0.0060 ;
        RECT -0.0160 0.2340 0.3240 0.2460 ;
    END
  END VDD
  PIN VSS
    DIRECTION INOUT ;
    USE GROUND ;
    PORT
      LAYER M0 ;
        RECT -0.0160 0.1140 0.3240 0.1260 ;
    END
  END VSS
  PIN Z
    DIRECTION OUTPUT ;
    USE SIGNAL ;
    PORT
      LAYER M1 ;
        RECT 0.0580 0.0160 0.0740 0.1040 ;
    END
  END Z
  PIN S
    DIRECTION INPUT ;
    USE SIGNAL ;
    PORT
      LAYER M1 ;
        RECT 0.1020 0.0400 0.1180 0.2000 ;
    END
  END S
  PIN B
    DIRECTION INPUT ;
    USE SIGNAL ;
    PORT
      LAYER M1 ;
        RECT 0.1460 0.0640 0.1620 0.1760 ;
    END
  END B
  PIN A
    DIRECTION INPUT ;
    USE SIGNAL ;
    PORT
      LAYER M1 ;
        RECT 0.2340 0.1840 0.2500 0.2000 ;
    END
  END A
  OBS
    LAYER M1 DESIGNRULEWIDTH 0 ;
      RECT 0.1900 0.0160 0.2060 0.1760 ;
      RECT 0.0140 0.0620 0.0300 0.1520 ;
      RECT 0.2780 0.0630 0.2940 0.1520 ;
      RECT 0.0580 0.1340 0.0740 0.2240 ;
      RECT 0.2340 0.1360 0.2500 0.1640 ;
      POLYGON 0.2940 0.1600 0.2940 0.2200 0.3080 0.2200 0.3080 0.2400 0.2700 0.2400 0.2700 0.2200 0.2780 0.2200 0.2780 0.1600 ;
      RECT 0.1820 0.2200 0.2140 0.2400 ;
      RECT 0.0000 0.2200 0.0380 0.2400 ;
    LAYER M0 DESIGNRULEWIDTH 0 ;
      RECT 0.1880 0.0200 0.2080 0.0300 ;
      RECT 0.0560 0.0200 0.0760 0.0300 ;
      RECT 0.1010 0.0420 0.1800 0.0540 ;
      RECT 0.1420 0.0660 0.2990 0.0780 ;
      RECT 0.0120 0.0660 0.0920 0.0780 ;
      RECT 0.1880 0.0900 0.2080 0.1000 ;
      RECT 0.0560 0.0900 0.0760 0.1000 ;
      RECT 0.2600 0.1400 0.2990 0.1500 ;
      RECT 0.0120 0.1400 0.2480 0.1500 ;
      RECT 0.2320 0.1620 0.2960 0.1740 ;
      RECT 0.1720 0.1620 0.2090 0.1740 ;
      RECT 0.1280 0.1620 0.1600 0.1740 ;
      RECT 0.2160 0.1860 0.2510 0.1980 ;
      RECT 0.0840 0.1860 0.1420 0.1980 ;
      RECT 0.2770 0.2100 0.2970 0.2200 ;
      RECT 0.1450 0.2100 0.2540 0.2200 ;
      RECT 0.0520 0.2100 0.1210 0.2200 ;
  END
END MUX2_X2

MACRO XOR2_X2
  CLASS CORE ;
  ORIGIN 0 0 ;
  FOREIGN XOR_X2 0 0 ;
  SYMMETRY X Y ;
  SITE i3d_nsfet3nm_2H_VDD ;
  SIZE 0.264 BY 0.24 ;
  PIN VDD
    DIRECTION INOUT ;
    USE POWER ;
    PORT
      LAYER M0 ;
        RECT -0.0160 -0.0060 0.2800 0.0060 ;
        RECT -0.0160 0.2340 0.2800 0.2460 ;
    END
  END VDD
  PIN VSS
    DIRECTION INOUT ;
    USE GROUND ;
    PORT
      LAYER M0 ;
        RECT -0.0160 0.1140 0.2800 0.1260 ;
    END
  END VSS
  PIN Z
    DIRECTION OUTPUT ;
    USE SIGNAL ;
    PORT
      LAYER M1 ;
        RECT 0.1460 0.0160 0.1620 0.0800 ;
    END
  END Z
  PIN A
    DIRECTION INPUT ;
    USE SIGNAL ;
    PORT
      LAYER M1 ;
        RECT 0.1460 0.0880 0.1620 0.1760 ;
    END
  END A
  PIN B
    DIRECTION INPUT ;
    USE SIGNAL ;
    PORT
      LAYER M1 ;
        RECT 0.1020 0.0880 0.1180 0.1760 ;
    END
  END B
  OBS
    LAYER M1 DESIGNRULEWIDTH 0 ;
      RECT 0.1900 0.0160 0.2060 0.0560 ;
      RECT 0.1020 0.0160 0.1180 0.0560 ;
      RECT 0.0140 0.0160 0.0300 0.1540 ;
      RECT 0.1900 0.0640 0.2060 0.1040 ;
      RECT 0.0580 0.0640 0.0740 0.1040 ;
      POLYGON 0.2060 0.1350 0.2060 0.1960 0.2340 0.1960 0.2340 0.1840 0.2500 0.1840 0.2500 0.1960 0.2640 0.1960 0.2640 0.2400 0.1820 0.2400 0.1820 0.1960 0.1900 0.1960 0.1900 0.1350 ;
      RECT 0.1460 0.1960 0.1620 0.2240 ;
      RECT 0.0000 0.1960 0.0820 0.2400 ;
    LAYER M0 DESIGNRULEWIDTH 0 ;
      RECT 0.1870 0.0200 0.2070 0.0300 ;
      RECT 0.1440 0.0200 0.1640 0.0300 ;
      RECT 0.1040 0.0200 0.1240 0.0300 ;
      RECT 0.0110 0.0200 0.0920 0.0300 ;
      RECT 0.1010 0.0420 0.2080 0.0540 ;
      RECT 0.0580 0.0660 0.2100 0.0780 ;
      RECT 0.1920 0.0900 0.2090 0.1000 ;
      RECT 0.1480 0.0900 0.1800 0.1000 ;
      RECT 0.0980 0.0900 0.1360 0.1000 ;
      RECT 0.0520 0.0900 0.0770 0.1000 ;
      RECT 0.0110 0.1400 0.2550 0.1500 ;
      RECT 0.1480 0.1620 0.2240 0.1740 ;
      RECT 0.0840 0.1620 0.1360 0.1740 ;
      RECT 0.1430 0.1860 0.2530 0.1980 ;
      RECT 0.2330 0.2100 0.2520 0.2200 ;
      RECT 0.1880 0.2100 0.2070 0.2200 ;
      RECT 0.0570 0.2100 0.1660 0.2200 ;
  END
END XOR2_X2

MACRO INV_X1
  CLASS CORE ;
  ORIGIN 0 0 ;
  FOREIGN INV_X1 0 0 ;
  SYMMETRY X Y ;
  SITE i3d_nsfet3nm ;
  SIZE 0.088 BY 0.12 ;
  PIN VDD
    DIRECTION INOUT ;
    USE POWER ;
    PORT
      LAYER M0 ;
        RECT -0.0160 0.1140 0.1040 0.1260 ;
    END
  END VDD
  PIN VSS
    DIRECTION INOUT ;
    USE GROUND ;
    PORT
      LAYER M0 ;
        RECT -0.0160 -0.0060 0.1040 0.0060 ;
    END
  END VSS
  PIN A
    DIRECTION INPUT ;
    USE SIGNAL ;
    PORT
      LAYER M1 ;
        RECT 0.0140 0.0160 0.0300 0.1040 ;
    END
  END A
  PIN ZN
    DIRECTION OUTPUT ;
    USE SIGNAL ;
    PORT
      LAYER M1 ;
        RECT 0.0580 0.0160 0.0740 0.1040 ;
    END
  END ZN
  OBS
    LAYER M0 DESIGNRULEWIDTH 0 ;
      RECT 0.0090 0.0200 0.0790 0.0300 ;
      RECT 0.0090 0.0420 0.0790 0.0540 ;
      RECT 0.0090 0.0660 0.0790 0.0780 ;
      RECT 0.0090 0.0900 0.0790 0.1000 ;
  END
END INV_X1


MACRO INV_X2
  CLASS CORE ;
  ORIGIN 0 0 ;
  FOREIGN INV_X2 0 0 ;
  SYMMETRY X Y ;
  SITE i3d_nsfet3nm ;
  SIZE 0.132 BY 0.12 ;
  PIN VDD
    DIRECTION INOUT ;
    USE POWER ;
    PORT
      LAYER M0 ;
        RECT -0.0160 0.1140 0.1480 0.1260 ;
    END
  END VDD
  PIN A
    DIRECTION INPUT ;
    USE SIGNAL ;
    PORT
      LAYER M1 ;
        RECT 0.0580 0.0160 0.0740 0.1040 ;
    END
  END A
  PIN ZN
    DIRECTION OUTPUT ;
    USE SIGNAL ;
    PORT
      LAYER M1 ;
        RECT 0.1020 0.0160 0.1180 0.1040 ;
    END
  END ZN
  PIN VSS
    DIRECTION INOUT ;
    USE GROUND ;
    PORT
      LAYER M0 ;
        RECT -0.0160 -0.0060 0.1480 0.0060 ;
    END
  END VSS
  OBS
    LAYER M1 DESIGNRULEWIDTH 0 ;
      RECT 0.0140 0.0160 0.0300 0.1040 ;
    LAYER M0 DESIGNRULEWIDTH 0 ;
      RECT 0.0090 0.0200 0.1230 0.0300 ;
      RECT 0.0090 0.0420 0.1230 0.0540 ;
      RECT 0.0090 0.0660 0.1230 0.0780 ;
      RECT 0.0090 0.0900 0.1230 0.1000 ;
  END
END INV_X2

MACRO INV_X32
  CLASS CORE ;
  ORIGIN 0 0 ;
  FOREIGN INV_X32 0 0 ;
  SYMMETRY X Y ;
  SITE i3d_nsfet3nm ;
  SIZE 1.452 BY 0.12 ;
  PIN VDD
    DIRECTION INOUT ;
    USE POWER ;
    PORT
      LAYER M0 ;
        RECT -0.0160 0.1140 1.4680 0.1260 ;
    END
  END VDD
  PIN VSS
    DIRECTION INOUT ;
    USE GROUND ;
    PORT
      LAYER M0 ;
        RECT -0.0160 -0.0060 1.4680 0.0060 ;
    END
  END VSS
  PIN A
    DIRECTION INPUT ;
    USE SIGNAL ;
    PORT
      LAYER M1 ;
        RECT 0.0580 0.0160 0.0740 0.1040 ;
    END
  END A
  PIN ZN
    DIRECTION OUTPUT ;
    USE SIGNAL ;
    PORT
      LAYER M1 ;
        RECT 0.1020 0.0160 0.1180 0.1040 ;
    END
  END ZN
  OBS
    LAYER M1 DESIGNRULEWIDTH 0 ;
      RECT 1.4220 0.0160 1.4380 0.1040 ;
      RECT 1.3780 0.0160 1.3940 0.1040 ;
      RECT 1.3340 0.0160 1.3500 0.1040 ;
      RECT 1.2900 0.0160 1.3060 0.1040 ;
      RECT 1.2460 0.0160 1.2620 0.1040 ;
      RECT 1.2020 0.0160 1.2180 0.1040 ;
      RECT 1.1580 0.0160 1.1740 0.1040 ;
      RECT 1.1140 0.0160 1.1300 0.1040 ;
      RECT 1.0700 0.0160 1.0860 0.1040 ;
      RECT 1.0260 0.0160 1.0420 0.1040 ;
      RECT 0.9820 0.0160 0.9980 0.1040 ;
      RECT 0.9380 0.0160 0.9540 0.1040 ;
      RECT 0.8940 0.0160 0.9100 0.1040 ;
      RECT 0.8500 0.0160 0.8660 0.1040 ;
      RECT 0.8060 0.0160 0.8220 0.1040 ;
      RECT 0.7620 0.0160 0.7780 0.1040 ;
      RECT 0.7180 0.0160 0.7340 0.1040 ;
      RECT 0.6740 0.0160 0.6900 0.1040 ;
      RECT 0.6300 0.0160 0.6460 0.1040 ;
      RECT 0.5860 0.0160 0.6020 0.1040 ;
      RECT 0.5420 0.0160 0.5580 0.1040 ;
      RECT 0.4980 0.0160 0.5140 0.1040 ;
      RECT 0.4540 0.0160 0.4700 0.1040 ;
      RECT 0.4100 0.0160 0.4260 0.1040 ;
      RECT 0.3660 0.0160 0.3820 0.1040 ;
      RECT 0.3220 0.0160 0.3380 0.1040 ;
      RECT 0.2780 0.0160 0.2940 0.1040 ;
      RECT 0.2340 0.0160 0.2500 0.1040 ;
      RECT 0.1900 0.0160 0.2060 0.1040 ;
      RECT 0.1460 0.0160 0.1620 0.1040 ;
      RECT 0.0140 0.0160 0.0300 0.1040 ;
    LAYER M0 DESIGNRULEWIDTH 0 ;
      RECT 0.0090 0.0200 1.4420 0.0300 ;
      RECT 0.0090 0.0420 1.4420 0.0540 ;
      RECT 0.0090 0.0660 1.4420 0.0780 ;
      RECT 0.0090 0.0900 1.4420 0.1000 ;
  END
END INV_X32



MACRO INV_X4
  CLASS CORE ;
  ORIGIN 0 0 ;
  FOREIGN INV_X4 0 0 ;
  SYMMETRY X Y ;
  SITE i3d_nsfet3nm ;
  SIZE 0.22 BY 0.12 ;
  PIN VDD
    DIRECTION INOUT ;
    USE POWER ;
    PORT
      LAYER M0 ;
        RECT -0.0160 0.1140 0.2360 0.1260 ;
    END
  END VDD
  PIN A
    DIRECTION INPUT ;
    USE SIGNAL ;
    PORT
      LAYER M1 ;
        RECT 0.0580 0.0160 0.0740 0.1040 ;
    END
  END A
  PIN ZN
    DIRECTION OUTPUT ;
    USE SIGNAL ;
    PORT
      LAYER M1 ;
        RECT 0.1020 0.0160 0.1180 0.1040 ;
    END
  END ZN
  PIN VSS
    DIRECTION INOUT ;
    USE GROUND ;
    PORT
      LAYER M0 ;
        RECT -0.0160 -0.0060 0.2360 0.0060 ;
    END
  END VSS
  OBS
    LAYER M1 DESIGNRULEWIDTH 0 ;
      RECT 0.1900 0.0160 0.2060 0.1040 ;
      RECT 0.1460 0.0160 0.1620 0.1040 ;
      RECT 0.0140 0.0160 0.0300 0.1040 ;
    LAYER M0 DESIGNRULEWIDTH 0 ;
      RECT 0.0090 0.0200 0.2100 0.0300 ;
      RECT 0.0090 0.0420 0.2100 0.0540 ;
      RECT 0.0090 0.0660 0.2100 0.0780 ;
      RECT 0.0090 0.0900 0.2100 0.1000 ;
  END
END INV_X4

MACRO INV_X8
  CLASS CORE ;
  ORIGIN 0 0 ;
  FOREIGN INV_X8 0 0 ;
  SYMMETRY X Y ;
  SITE i3d_nsfet3nm ;
  SIZE 0.396 BY 0.12 ;
  PIN VDD
    DIRECTION INOUT ;
    USE POWER ;
    PORT
      LAYER M0 ;
        RECT -0.0160 0.1140 0.4120 0.1260 ;
    END
  END VDD
  PIN A
    DIRECTION INPUT ;
    USE SIGNAL ;
    PORT
      LAYER M1 ;
        RECT 0.0580 0.0160 0.0740 0.1040 ;
    END
  END A
  PIN ZN
    DIRECTION OUTPUT ;
    USE SIGNAL ;
    PORT
      LAYER M1 ;
        RECT 0.1020 0.0160 0.1180 0.1040 ;
    END
  END ZN
  PIN VSS
    DIRECTION INOUT ;
    USE GROUND ;
    PORT
      LAYER M0 ;
        RECT -0.0160 -0.0060 0.4120 0.0060 ;
    END
  END VSS
  OBS
    LAYER M1 DESIGNRULEWIDTH 0 ;
      RECT 0.3660 0.0160 0.3820 0.1040 ;
      RECT 0.3220 0.0160 0.3380 0.1040 ;
      RECT 0.2780 0.0160 0.2940 0.1040 ;
      RECT 0.2340 0.0160 0.2500 0.1040 ;
      RECT 0.1900 0.0160 0.2060 0.1040 ;
      RECT 0.1460 0.0160 0.1620 0.1040 ;
      RECT 0.0140 0.0160 0.0300 0.1040 ;
    LAYER M0 DESIGNRULEWIDTH 0 ;
      RECT 0.0090 0.0200 0.3860 0.0300 ;
      RECT 0.0090 0.0420 0.3860 0.0540 ;
      RECT 0.0090 0.0660 0.3860 0.0780 ;
      RECT 0.0090 0.0900 0.3860 0.1000 ;
  END
END INV_X8

MACRO NOR2_X1
  CLASS CORE ;
  ORIGIN 0 0 ;
  FOREIGN NOR2_X1 0 0 ;
  SYMMETRY X Y ;
  SITE i3d_nsfet3nm ;
  SIZE 0.132 BY 0.12 ;
  PIN VDD
    DIRECTION INOUT ;
    USE POWER ;
    PORT
      LAYER M0 ;
        RECT -0.0160 0.1140 0.1480 0.1260 ;
    END
  END VDD
  PIN VSS
    DIRECTION INOUT ;
    USE GROUND ;
    PORT
      LAYER M0 ;
        RECT -0.0160 -0.0060 0.1480 0.0060 ;
    END
  END VSS
  PIN A1
    DIRECTION INPUT ;
    USE SIGNAL ;
    PORT
      LAYER M1 ;
        RECT 0.0140 0.0160 0.0300 0.1040 ;
    END
  END A1
  PIN A2
    DIRECTION INPUT ;
    USE SIGNAL ;
    PORT
      LAYER M1 ;
        RECT 0.0580 0.0160 0.0740 0.1040 ;
    END
  END A2
  PIN ZN
    DIRECTION OUTPUT ;
    USE SIGNAL ;
    PORT
      LAYER M1 ;
        RECT 0.1020 0.0160 0.1180 0.1040 ;
    END
  END ZN
  OBS
    LAYER M0 DESIGNRULEWIDTH 0 ;
      RECT 0.0090 0.0200 0.1230 0.0300 ;
      RECT 0.0090 0.0420 0.1230 0.0540 ;
      RECT 0.0090 0.0660 0.1230 0.0780 ;
      RECT 0.0090 0.0900 0.1230 0.1000 ;
  END
END NOR2_X1

MACRO NOR2_X2
  CLASS CORE ;
  ORIGIN 0 0 ;
  FOREIGN NOR2_X2 0 0 ;
  SYMMETRY X Y ;
  SITE i3d_nsfet3nm ;
  SIZE 0.22 BY 0.12 ;
  PIN VDD
    DIRECTION INOUT ;
    USE POWER ;
    PORT
      LAYER M0 ;
        RECT -0.0160 0.1140 0.2360 0.1260 ;
    END
  END VDD
  PIN VSS
    DIRECTION INOUT ;
    USE GROUND ;
    PORT
      LAYER M0 ;
        RECT -0.0160 -0.0060 0.2360 0.0060 ;
    END
  END VSS
  PIN ZN
    DIRECTION OUTPUT ;
    USE SIGNAL ;
    PORT
      LAYER M1 ;
        RECT 0.1460 0.0160 0.1620 0.1040 ;
    END
  END ZN
  PIN A2
    DIRECTION INPUT ;
    USE SIGNAL ;
    PORT
      LAYER M1 ;
        RECT 0.1900 0.0400 0.2060 0.0560 ;
    END
  END A2
  PIN A1
    DIRECTION INPUT ;
    USE SIGNAL ;
    PORT
      LAYER M1 ;
        RECT 0.0140 0.0400 0.0300 0.0560 ;
    END
  END A1
  OBS
    LAYER M1 DESIGNRULEWIDTH 0 ;
      RECT 0.1020 0.0640 0.1180 0.1040 ;
      RECT 0.1900 0.0760 0.2060 0.1040 ;
      RECT 0.0140 0.0760 0.0300 0.1040 ;
    LAYER M0 DESIGNRULEWIDTH 0 ;
      RECT 0.0090 0.0200 0.2100 0.0300 ;
      RECT 0.1220 0.0420 0.2080 0.0540 ;
      RECT 0.0090 0.0420 0.0950 0.0540 ;
      RECT 0.0090 0.0660 0.2090 0.0780 ;
      RECT 0.1850 0.0900 0.2090 0.1000 ;
      RECT 0.1430 0.0900 0.1670 0.1000 ;
      RECT 0.0990 0.0900 0.1230 0.1000 ;
      RECT 0.0110 0.0900 0.0350 0.1000 ;
  END
END NOR2_X2

MACRO NOR2_X4
  CLASS CORE ;
  ORIGIN 0 0 ;
  FOREIGN NOR2_X4 0 0 ;
  SYMMETRY X Y ;
  SITE i3d_nsfet3nm ;
  SIZE 0.396 BY 0.12 ;
  PIN VDD
    DIRECTION INOUT ;
    USE POWER ;
    PORT
      LAYER M0 ;
        RECT -0.0160 0.1140 0.4120 0.1260 ;
    END
  END VDD
  PIN VSS
    DIRECTION INOUT ;
    USE GROUND ;
    PORT
      LAYER M0 ;
        RECT -0.0160 -0.0060 0.4120 0.0060 ;
    END
  END VSS
  PIN A2
    DIRECTION INPUT ;
    USE SIGNAL ;
    PORT
      LAYER M1 ;
        RECT 0.3660 0.0400 0.3820 0.0560 ;
    END
  END A2
  PIN ZN
    DIRECTION OUTPUT ;
    USE SIGNAL ;
    PORT
      LAYER M1 ;
        RECT 0.3220 0.0160 0.3380 0.1040 ;
    END
  END ZN
  PIN A1
    DIRECTION INPUT ;
    USE SIGNAL ;
    PORT
      LAYER M1 ;
        RECT 0.0140 0.0400 0.0300 0.0560 ;
    END
  END A1
  OBS
    LAYER M0 DESIGNRULEWIDTH 0 ;
      RECT 0.0090 0.0200 0.3850 0.0300 ;
      RECT 0.2070 0.0420 0.3840 0.0540 ;
      RECT 0.0090 0.0420 0.1820 0.0540 ;
      RECT 0.0090 0.0660 0.3840 0.0780 ;
      RECT 0.2290 0.0900 0.3430 0.1000 ;
  END
END NOR2_X4

MACRO NOR3_X1
  CLASS CORE ;
  ORIGIN 0 0 ;
  FOREIGN NOR3_X1 0 0 ;
  SYMMETRY X Y ;
  SITE i3d_nsfet3nm ;
  SIZE 0.176 BY 0.12 ;
  PIN VDD
    DIRECTION INOUT ;
    USE POWER ;
    PORT
      LAYER M0 ;
        RECT -0.0160 0.1140 0.1920 0.1260 ;
    END
  END VDD
  PIN VSS
    DIRECTION INOUT ;
    USE GROUND ;
    PORT
      LAYER M0 ;
        RECT -0.0160 -0.0060 0.1920 0.0060 ;
    END
  END VSS
  PIN ZN
    DIRECTION OUTPUT ;
    USE SIGNAL ;
    PORT
      LAYER M1 ;
        RECT 0.1460 0.0160 0.1620 0.1040 ;
    END
  END ZN
  PIN A1
    DIRECTION INPUT ;
    USE SIGNAL ;
    PORT
      LAYER M1 ;
        RECT 0.0140 0.0640 0.0300 0.0800 ;
    END
  END A1
  PIN A2
    DIRECTION INPUT ;
    USE SIGNAL ;
    PORT
      LAYER M1 ;
        RECT 0.0580 0.0400 0.0740 0.0560 ;
    END
  END A2
  PIN A3
    DIRECTION INPUT ;
    USE SIGNAL ;
    PORT
      LAYER M1 ;
        RECT 0.1020 0.0640 0.1180 0.0800 ;
    END
  END A3
  OBS
    LAYER M0 DESIGNRULEWIDTH 0 ;
      RECT 0.0090 0.0200 0.1660 0.0300 ;
      RECT 0.0090 0.0420 0.1230 0.0540 ;
      RECT 0.0970 0.0660 0.1420 0.0780 ;
      RECT 0.0090 0.0660 0.0540 0.0780 ;
      RECT 0.0090 0.0900 0.1650 0.1000 ;
  END
END NOR3_X1

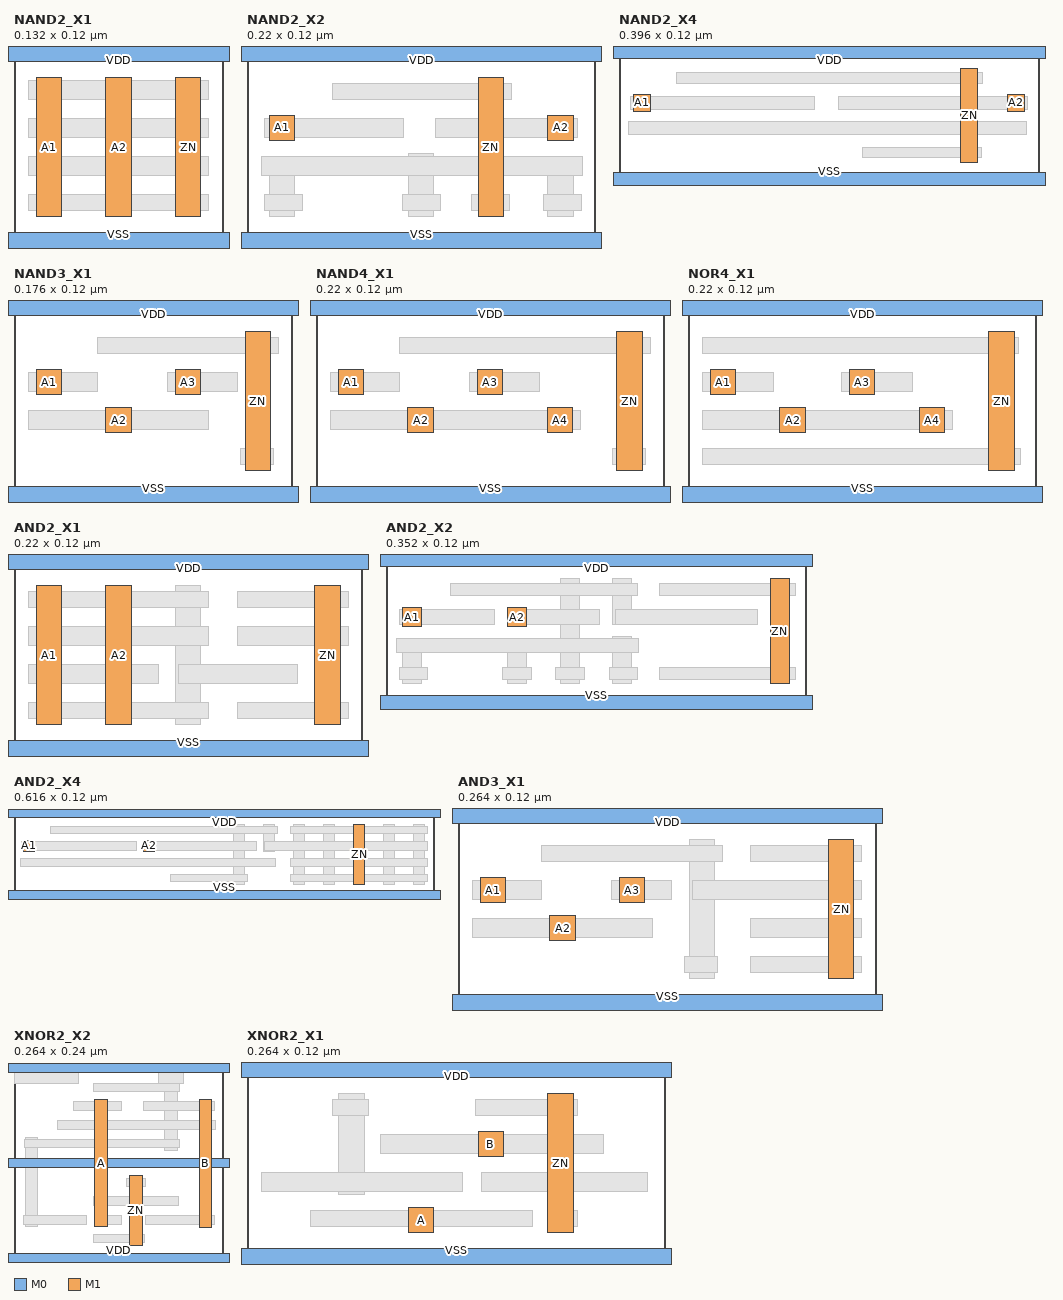
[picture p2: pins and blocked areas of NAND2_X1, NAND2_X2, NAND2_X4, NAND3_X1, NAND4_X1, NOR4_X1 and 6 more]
MACRO NAND2_X1
  CLASS CORE ;
  ORIGIN 0 0 ;
  FOREIGN NAND2_X1 0 0 ;
  SYMMETRY X Y ;
  SITE i3d_nsfet3nm ;
  SIZE 0.132 BY 0.12 ;
  PIN VDD
    DIRECTION INOUT ;
    USE POWER ;
    PORT
      LAYER M0 ;
        RECT -0.0160 0.1140 0.1480 0.1260 ;
    END
  END VDD
  PIN A2
    DIRECTION INPUT ;
    USE SIGNAL ;
    PORT
      LAYER M1 ;
        RECT 0.0580 0.0160 0.0740 0.1040 ;
    END
  END A2
  PIN A1
    DIRECTION INPUT ;
    USE SIGNAL ;
    PORT
      LAYER M1 ;
        RECT 0.0140 0.0160 0.0300 0.1040 ;
    END
  END A1
  PIN ZN
    DIRECTION OUTPUT ;
    USE SIGNAL ;
    PORT
      LAYER M1 ;
        RECT 0.1020 0.0160 0.1180 0.1040 ;
    END
  END ZN
  PIN VSS
    DIRECTION INOUT ;
    USE GROUND ;
    PORT
      LAYER M0 ;
        RECT -0.0160 -0.0060 0.1480 0.0060 ;
    END
  END VSS
  OBS
    LAYER M0 DESIGNRULEWIDTH 0 ;
      RECT 0.0090 0.0200 0.1230 0.0300 ;
      RECT 0.0090 0.0420 0.1230 0.0540 ;
      RECT 0.0090 0.0660 0.1230 0.0780 ;
      RECT 0.0090 0.0900 0.1230 0.1020 ;
  END
END NAND2_X1

MACRO NAND2_X2
  CLASS CORE ;
  ORIGIN 0 0 ;
  FOREIGN NAND2_X2 0 0 ;
  SYMMETRY X Y ;
  SITE i3d_nsfet3nm ;
  SIZE 0.22 BY 0.12 ;
  PIN VDD
    DIRECTION INOUT ;
    USE POWER ;
    PORT
      LAYER M0 ;
        RECT -0.0160 0.1140 0.2360 0.1260 ;
    END
  END VDD
  PIN VSS
    DIRECTION INOUT ;
    USE GROUND ;
    PORT
      LAYER M0 ;
        RECT -0.0160 -0.0060 0.2360 0.0060 ;
    END
  END VSS
  PIN A1
    DIRECTION INPUT ;
    USE SIGNAL ;
    PORT
      LAYER M1 ;
        RECT 0.0140 0.0640 0.0300 0.0800 ;
    END
  END A1
  PIN A2
    DIRECTION INPUT ;
    USE SIGNAL ;
    PORT
      LAYER M1 ;
        RECT 0.1900 0.0640 0.2060 0.0800 ;
    END
  END A2
  PIN ZN
    DIRECTION OUTPUT ;
    USE SIGNAL ;
    PORT
      LAYER M1 ;
        RECT 0.1460 0.0160 0.1620 0.1040 ;
    END
  END ZN
  OBS
    LAYER M1 DESIGNRULEWIDTH 0 ;
      RECT 0.1900 0.0160 0.2060 0.0440 ;
      RECT 0.1020 0.0160 0.1180 0.0560 ;
      RECT 0.0140 0.0160 0.0300 0.0440 ;
    LAYER M0 DESIGNRULEWIDTH 0 ;
      RECT 0.1870 0.0200 0.2110 0.0300 ;
      RECT 0.1420 0.0200 0.1660 0.0300 ;
      RECT 0.0980 0.0200 0.1220 0.0300 ;
      RECT 0.0110 0.0200 0.0350 0.0300 ;
      RECT 0.0090 0.0420 0.2120 0.0540 ;
      RECT 0.1190 0.0660 0.2090 0.0780 ;
      RECT 0.0110 0.0660 0.0990 0.0780 ;
      RECT 0.0540 0.0900 0.1670 0.1000 ;
  END
END NAND2_X2

MACRO NAND2_X4
  CLASS CORE ;
  ORIGIN 0 0 ;
  FOREIGN NAND2_X4 0 0 ;
  SYMMETRY X Y ;
  SITE i3d_nsfet3nm ;
  SIZE 0.396 BY 0.12 ;
  PIN VDD
    DIRECTION INOUT ;
    USE POWER ;
    PORT
      LAYER M0 ;
        RECT -0.0160 0.1140 0.4120 0.1260 ;
    END
  END VDD
  PIN VSS
    DIRECTION INOUT ;
    USE GROUND ;
    PORT
      LAYER M0 ;
        RECT -0.0160 -0.0060 0.4120 0.0060 ;
    END
  END VSS
  PIN A1
    DIRECTION INPUT ;
    USE SIGNAL ;
    PORT
      LAYER M1 ;
        RECT 0.0140 0.0640 0.0300 0.0800 ;
    END
  END A1
  PIN A2
    DIRECTION INPUT ;
    USE SIGNAL ;
    PORT
      LAYER M1 ;
        RECT 0.3660 0.0640 0.3820 0.0800 ;
    END
  END A2
  PIN ZN
    DIRECTION OUTPUT ;
    USE SIGNAL ;
    PORT
      LAYER M1 ;
        RECT 0.3220 0.0160 0.3380 0.1040 ;
    END
  END ZN
  OBS
    LAYER M0 DESIGNRULEWIDTH 0 ;
      RECT 0.2300 0.0200 0.3420 0.0300 ;
      RECT 0.0090 0.0420 0.3840 0.0540 ;
      RECT 0.2070 0.0660 0.3850 0.0780 ;
      RECT 0.0110 0.0660 0.1840 0.0780 ;
      RECT 0.0540 0.0900 0.3430 0.1000 ;
  END
END NAND2_X4

MACRO NAND3_X1
  CLASS CORE ;
  ORIGIN 0 0 ;
  FOREIGN NAND3_X1 0 0 ;
  SYMMETRY X Y ;
  SITE i3d_nsfet3nm ;
  SIZE 0.176 BY 0.12 ;
  PIN VDD
    DIRECTION INOUT ;
    USE POWER ;
    PORT
      LAYER M0 ;
        RECT -0.0160 0.1140 0.1920 0.1260 ;
    END
  END VDD
  PIN VSS
    DIRECTION INOUT ;
    USE GROUND ;
    PORT
      LAYER M0 ;
        RECT -0.0160 -0.0060 0.1920 0.0060 ;
    END
  END VSS
  PIN A1
    DIRECTION INPUT ;
    USE SIGNAL ;
    PORT
      LAYER M1 ;
        RECT 0.0140 0.0640 0.0300 0.0800 ;
    END
  END A1
  PIN A3
    DIRECTION INPUT ;
    USE SIGNAL ;
    PORT
      LAYER M1 ;
        RECT 0.1020 0.0640 0.1180 0.0800 ;
    END
  END A3
  PIN A2
    DIRECTION INPUT ;
    USE SIGNAL ;
    PORT
      LAYER M1 ;
        RECT 0.0580 0.0400 0.0740 0.0560 ;
    END
  END A2
  PIN ZN
    DIRECTION OUTPUT ;
    USE SIGNAL ;
    PORT
      LAYER M1 ;
        RECT 0.1460 0.0160 0.1620 0.1040 ;
    END
  END ZN
  OBS
    LAYER M0 DESIGNRULEWIDTH 0 ;
      RECT 0.1430 0.0200 0.1640 0.0300 ;
      RECT 0.0090 0.0420 0.1230 0.0540 ;
      RECT 0.0970 0.0660 0.1410 0.0780 ;
      RECT 0.0090 0.0660 0.0530 0.0780 ;
      RECT 0.0530 0.0900 0.1670 0.1000 ;
  END
END NAND3_X1

MACRO NAND4_X1
  CLASS CORE ;
  ORIGIN 0 0 ;
  FOREIGN NAND4_X1 0 0 ;
  SYMMETRY X Y ;
  SITE i3d_nsfet3nm ;
  SIZE 0.22 BY 0.12 ;
  PIN VSS
    DIRECTION INOUT ;
    USE GROUND ;
    PORT
      LAYER M0 ;
        RECT -0.0160 -0.0060 0.2360 0.0060 ;
    END
  END VSS
  PIN VDD
    DIRECTION INOUT ;
    USE POWER ;
    PORT
      LAYER M0 ;
        RECT -0.0160 0.1140 0.2360 0.1260 ;
    END
  END VDD
  PIN A1
    DIRECTION INPUT ;
    USE SIGNAL ;
    PORT
      LAYER M1 ;
        RECT 0.0140 0.0640 0.0300 0.0800 ;
    END
  END A1
  PIN A2
    DIRECTION INPUT ;
    USE SIGNAL ;
    PORT
      LAYER M1 ;
        RECT 0.0580 0.0400 0.0740 0.0560 ;
    END
  END A2
  PIN A3
    DIRECTION INPUT ;
    USE SIGNAL ;
    PORT
      LAYER M1 ;
        RECT 0.1020 0.0640 0.1180 0.0800 ;
    END
  END A3
  PIN A4
    DIRECTION INPUT ;
    USE SIGNAL ;
    PORT
      LAYER M1 ;
        RECT 0.1460 0.0400 0.1620 0.0560 ;
    END
  END A4
  PIN ZN
    DIRECTION OUTPUT ;
    USE SIGNAL ;
    PORT
      LAYER M1 ;
        RECT 0.1900 0.0160 0.2060 0.1040 ;
    END
  END ZN
  OBS
    LAYER M0 DESIGNRULEWIDTH 0 ;
      RECT 0.1870 0.0200 0.2080 0.0300 ;
      RECT 0.0090 0.0420 0.1670 0.0540 ;
      RECT 0.0090 0.0660 0.0530 0.0780 ;
      RECT 0.0970 0.0660 0.1410 0.0780 ;
      RECT 0.0530 0.0900 0.2110 0.1000 ;
  END
END NAND4_X1

MACRO NOR4_X1
  CLASS CORE ;
  ORIGIN 0 0 ;
  FOREIGN NOR4_X1 0 0 ;
  SYMMETRY X Y ;
  SITE i3d_nsfet3nm ;
  SIZE 0.22 BY 0.12 ;
  PIN VSS
    DIRECTION INOUT ;
    USE GROUND ;
    PORT
      LAYER M0 ;
        RECT -0.0160 -0.0060 0.2360 0.0060 ;
    END
  END VSS
  PIN VDD
    DIRECTION INOUT ;
    USE POWER ;
    PORT
      LAYER M0 ;
        RECT -0.0160 0.1140 0.2360 0.1260 ;
    END
  END VDD
  PIN A1
    DIRECTION INPUT ;
    USE SIGNAL ;
    PORT
      LAYER M1 ;
        RECT 0.0140 0.0640 0.0300 0.0800 ;
    END
  END A1
  PIN A2
    DIRECTION INPUT ;
    USE SIGNAL ;
    PORT
      LAYER M1 ;
        RECT 0.0580 0.0400 0.0740 0.0560 ;
    END
  END A2
  PIN A3
    DIRECTION INPUT ;
    USE SIGNAL ;
    PORT
      LAYER M1 ;
        RECT 0.1020 0.0640 0.1180 0.0800 ;
    END
  END A3
  PIN A4
    DIRECTION INPUT ;
    USE SIGNAL ;
    PORT
      LAYER M1 ;
        RECT 0.1460 0.0400 0.1620 0.0560 ;
    END
  END A4
  PIN ZN
    DIRECTION OUTPUT ;
    USE SIGNAL ;
    PORT
      LAYER M1 ;
        RECT 0.1900 0.0160 0.2060 0.1040 ;
    END
  END ZN
  OBS
    LAYER M0 DESIGNRULEWIDTH 0 ;
      RECT 0.0090 0.0200 0.2100 0.0300 ;
      RECT 0.0090 0.0420 0.1670 0.0540 ;
      RECT 0.0090 0.0660 0.0540 0.0780 ;
      RECT 0.0970 0.0660 0.1420 0.0780 ;
      RECT 0.0090 0.0900 0.2090 0.1000 ;
  END
END NOR4_X1

MACRO AND2_X1
  CLASS CORE ;
  ORIGIN 0 0 ;
  FOREIGN AND2_X1 0 0 ;
  SYMMETRY X Y ;
  SITE i3d_nsfet3nm ;
  SIZE 0.22 BY 0.12 ;
  PIN A1
    DIRECTION INPUT ;
    USE SIGNAL ;
    PORT
      LAYER M1 ;
        RECT 0.0140 0.0160 0.0300 0.1040 ;
    END
  END A1
  PIN A2
    DIRECTION INPUT ;
    USE SIGNAL ;
    PORT
      LAYER M1 ;
        RECT 0.0580 0.0160 0.0740 0.1040 ;
    END
  END A2
  PIN VDD
    DIRECTION INOUT ;
    USE POWER ;
    PORT
      LAYER M0 ;
        RECT -0.0160 0.1140 0.2360 0.1260 ;
    END
  END VDD
  PIN VSS
    DIRECTION INOUT ;
    USE GROUND ;
    PORT
      LAYER M0 ;
        RECT -0.0160 -0.0060 0.2360 0.0060 ;
    END
  END VSS
  PIN ZN
    DIRECTION OUTPUT ;
    USE SIGNAL ;
    PORT
      LAYER M1 ;
        RECT 0.1900 0.0160 0.2060 0.1040 ;
    END
  END ZN
  OBS
    LAYER M1 DESIGNRULEWIDTH 0 ;
      RECT 0.1020 0.0160 0.1180 0.1040 ;
    LAYER M0 DESIGNRULEWIDTH 0 ;
      RECT 0.1410 0.0200 0.2110 0.0300 ;
      RECT 0.0090 0.0200 0.1230 0.0300 ;
      RECT 0.1040 0.0420 0.1790 0.0540 ;
      RECT 0.0090 0.0420 0.0910 0.0540 ;
      RECT 0.1410 0.0660 0.2110 0.0780 ;
      RECT 0.0090 0.0660 0.1230 0.0780 ;
      RECT 0.1410 0.0900 0.2110 0.1000 ;
      RECT 0.0090 0.0900 0.1230 0.1000 ;
  END
END AND2_X1

MACRO AND2_X2
  CLASS CORE ;
  ORIGIN 0 0 ;
  FOREIGN AND2_X2 0 0 ;
  SYMMETRY X Y ;
  SITE i3d_nsfet3nm ;
  SIZE 0.352 BY 0.12 ;
  PIN A1
    DIRECTION INPUT ;
    USE SIGNAL ;
    PORT
      LAYER M1 ;
        RECT 0.0140 0.0640 0.0300 0.0800 ;
    END
  END A1
  PIN A2
    DIRECTION INPUT ;
    USE SIGNAL ;
    PORT
      LAYER M1 ;
        RECT 0.1020 0.0640 0.1180 0.0800 ;
    END
  END A2
  PIN ZN
    DIRECTION OUTPUT ;
    USE SIGNAL ;
    PORT
      LAYER M1 ;
        RECT 0.3220 0.0160 0.3380 0.1040 ;
    END
  END ZN
  PIN VDD
    DIRECTION INOUT ;
    USE POWER ;
    PORT
      LAYER M0 ;
        RECT -0.0160 0.1140 0.3680 0.1260 ;
    END
  END VDD
  PIN VSS
    DIRECTION INOUT ;
    USE GROUND ;
    PORT
      LAYER M0 ;
        RECT -0.0160 -0.0060 0.3680 0.0060 ;
    END
  END VSS
  OBS
    LAYER M1 ;
      RECT 0.1900 0.0160 0.2060 0.0560 ;
      RECT 0.1460 0.0160 0.1620 0.1040 ;
      RECT 0.1020 0.0160 0.1180 0.0440 ;
      RECT 0.0140 0.0160 0.0300 0.0440 ;
      RECT 0.1900 0.0660 0.2060 0.1040 ;
    LAYER M0 DESIGNRULEWIDTH 0 ;
      RECT 0.2290 0.0200 0.3430 0.0300 ;
      RECT 0.1870 0.0200 0.2110 0.0300 ;
      RECT 0.1420 0.0200 0.1660 0.0300 ;
      RECT 0.0980 0.0200 0.1220 0.0300 ;
      RECT 0.0110 0.0200 0.0350 0.0300 ;
      RECT 0.0090 0.0420 0.2120 0.0540 ;
      RECT 0.1920 0.0660 0.3110 0.0780 ;
      RECT 0.1040 0.0660 0.1790 0.0780 ;
      RECT 0.0110 0.0660 0.0910 0.0780 ;
      RECT 0.2290 0.0900 0.3430 0.1000 ;
      RECT 0.0540 0.0900 0.2110 0.1000 ;
  END
END AND2_X2

MACRO AND2_X4
  CLASS CORE ;
  ORIGIN 0 0 ;
  FOREIGN AND2_X4 0 0 ;
  SYMMETRY X Y ;
  SITE i3d_nsfet3nm ;
  SIZE 0.616 BY 0.12 ;
  PIN A1
    DIRECTION INPUT ;
    USE SIGNAL ;
    PORT
      LAYER M1 ;
        RECT 0.0140 0.0640 0.0300 0.0800 ;
    END
  END A1
  PIN A2
    DIRECTION INPUT ;
    USE SIGNAL ;
    PORT
      LAYER M1 ;
        RECT 0.1900 0.0640 0.2060 0.0800 ;
    END
  END A2
  PIN ZN
    DIRECTION OUTPUT ;
    USE SIGNAL ;
    PORT
      LAYER M1 ;
        RECT 0.4980 0.0160 0.5140 0.1040 ;
    END
  END ZN
  PIN VDD
    DIRECTION INOUT ;
    USE POWER ;
    PORT
      LAYER M0 ;
        RECT -0.0160 0.1140 0.6320 0.1260 ;
    END
  END VDD
  PIN VSS
    DIRECTION INOUT ;
    USE GROUND ;
    PORT
      LAYER M0 ;
        RECT -0.0160 -0.0060 0.6320 0.0060 ;
    END
  END VSS
  OBS
    LAYER M1 DESIGNRULEWIDTH 0 ;
      RECT 0.5860 0.0160 0.6020 0.1040 ;
      RECT 0.5420 0.0160 0.5580 0.1040 ;
      RECT 0.4540 0.0160 0.4700 0.1040 ;
      RECT 0.4100 0.0160 0.4260 0.1040 ;
      RECT 0.3220 0.0160 0.3380 0.1040 ;
      RECT 0.3660 0.0640 0.3820 0.1040 ;
    LAYER M0 DESIGNRULEWIDTH 0 ;
      RECT 0.4050 0.0200 0.6060 0.0300 ;
      RECT 0.2300 0.0200 0.3420 0.0300 ;
      RECT 0.4050 0.0420 0.6060 0.0540 ;
      RECT 0.0090 0.0420 0.3840 0.0540 ;
      RECT 0.3680 0.0660 0.6060 0.0780 ;
      RECT 0.1920 0.0660 0.3550 0.0780 ;
      RECT 0.0110 0.0660 0.1790 0.0780 ;
      RECT 0.4050 0.0900 0.6060 0.1000 ;
      RECT 0.0540 0.0900 0.3870 0.1000 ;
  END
END AND2_X4

MACRO AND3_X1
  CLASS CORE ;
  ORIGIN 0 0 ;
  FOREIGN AND3_X1 0 0 ;
  SYMMETRY X Y ;
  SITE i3d_nsfet3nm ;
  SIZE 0.264 BY 0.12 ;
  PIN VDD
    DIRECTION INOUT ;
    USE POWER ;
    PORT
      LAYER M0 ;
        RECT -0.0160 0.1140 0.2800 0.1260 ;
    END
  END VDD
  PIN VSS
    DIRECTION INOUT ;
    USE GROUND ;
    PORT
      LAYER M0 ;
        RECT -0.0160 -0.0060 0.2800 0.0060 ;
    END
  END VSS
  PIN A1
    DIRECTION INPUT ;
    USE SIGNAL ;
    PORT
      LAYER M1 ;
        RECT 0.0140 0.0640 0.0300 0.0800 ;
    END
  END A1
  PIN A2
    DIRECTION INPUT ;
    USE SIGNAL ;
    PORT
      LAYER M1 ;
        RECT 0.0580 0.0400 0.0740 0.0560 ;
    END
  END A2
  PIN A3
    DIRECTION INPUT ;
    USE SIGNAL ;
    PORT
      LAYER M1 ;
        RECT 0.1020 0.0640 0.1180 0.0800 ;
    END
  END A3
  PIN ZN
    DIRECTION OUTPUT ;
    USE SIGNAL ;
    PORT
      LAYER M1 ;
        RECT 0.2340 0.0160 0.2500 0.1040 ;
    END
  END ZN
  OBS
    LAYER M1 DESIGNRULEWIDTH 0 ;
      RECT 0.1460 0.0160 0.1620 0.1040 ;
    LAYER M0 DESIGNRULEWIDTH 0 ;
      RECT 0.1850 0.0200 0.2550 0.0300 ;
      RECT 0.1430 0.0200 0.1640 0.0300 ;
      RECT 0.1850 0.0420 0.2550 0.0540 ;
      RECT 0.0090 0.0420 0.1230 0.0540 ;
      RECT 0.1480 0.0660 0.2550 0.0780 ;
      RECT 0.0970 0.0660 0.1350 0.0780 ;
      RECT 0.0090 0.0660 0.0530 0.0780 ;
      RECT 0.1850 0.0900 0.2550 0.1000 ;
      RECT 0.0530 0.0900 0.1670 0.1000 ;
  END
END AND3_X1

MACRO XNOR2_X2
  CLASS CORE ;
  ORIGIN 0 0 ;
  FOREIGN XNOR2X2 0 0 ;
  SYMMETRY X Y ;
  SITE i3d_nsfet3nm_2H_VDD ;
  SIZE 0.264 BY 0.24 ;
  PIN VDD
    DIRECTION INOUT ;
    USE POWER ;
    PORT
      LAYER M0 ;
        RECT -0.0160 -0.0060 0.2800 0.0060 ;
        RECT -0.0160 0.2340 0.2800 0.2460 ;
    END
  END VDD
  PIN VSS
    DIRECTION INOUT ;
    USE GROUND ;
    PORT
      LAYER M0 ;
        RECT -0.0160 0.1140 0.2800 0.1260 ;
    END
  END VSS
  PIN A
    DIRECTION INPUT ;
    USE SIGNAL ;
    PORT
      LAYER M1 ;
        RECT 0.1020 0.0400 0.1180 0.2000 ;
    END
  END A
  PIN B
    DIRECTION INPUT ;
    USE SIGNAL ;
    PORT
      LAYER M1 ;
        RECT 0.2340 0.0380 0.2500 0.2000 ;
    END
  END B
  PIN ZN
    DIRECTION OUTPUT ;
    USE SIGNAL ;
    PORT
      LAYER M1 ;
        RECT 0.1460 0.0160 0.1620 0.1040 ;
    END
  END ZN
  OBS
    LAYER M1 DESIGNRULEWIDTH 0 ;
      RECT 0.0140 0.0400 0.0300 0.1520 ;
      POLYGON 0.2060 0.1360 0.2060 0.2200 0.2140 0.2200 0.2140 0.2400 0.1820 0.2400 0.1820 0.2200 0.1900 0.2200 0.1900 0.1360 ;
      RECT 0.0000 0.2200 0.0820 0.2400 ;
    LAYER M0 DESIGNRULEWIDTH 0 ;
      RECT 0.1000 0.0200 0.1650 0.0300 ;
      RECT 0.1660 0.0420 0.2530 0.0540 ;
      RECT 0.1040 0.0420 0.1360 0.0540 ;
      RECT 0.0120 0.0420 0.0920 0.0540 ;
      RECT 0.1000 0.0660 0.2080 0.0780 ;
      RECT 0.1420 0.0900 0.1660 0.1000 ;
      RECT 0.0130 0.1400 0.2090 0.1500 ;
      RECT 0.0550 0.1620 0.2540 0.1740 ;
      RECT 0.1630 0.1860 0.2530 0.1980 ;
      RECT 0.0750 0.1860 0.1360 0.1980 ;
      RECT 0.1000 0.2100 0.2090 0.2200 ;
  END
END XNOR2_X2

MACRO XNOR2_X1
  CLASS CORE ;
  ORIGIN 0 0 ;
  FOREIGN XNOR2_X1 0 0 ;
  SYMMETRY X Y ;
  SITE i3d_nsfet3nm ;
  SIZE 0.264 BY 0.12 ;
  PIN VDD
    DIRECTION INOUT ;
    USE POWER ;
    PORT
      LAYER M0 ;
        RECT -0.0160 0.1140 0.2800 0.1260 ;
    END
  END VDD
  PIN VSS
    DIRECTION INOUT ;
    USE GROUND ;
    PORT
      LAYER M0 ;
        RECT -0.0160 -0.0060 0.2800 0.0060 ;
    END
  END VSS
  PIN A
    DIRECTION INPUT ;
    USE SIGNAL ;
    PORT
      LAYER M1 ;
        RECT 0.1020 0.0160 0.1180 0.0320 ;
    END
  END A
  PIN B
    DIRECTION INPUT ;
    USE SIGNAL ;
    PORT
      LAYER M1 ;
        RECT 0.1460 0.0640 0.1620 0.0800 ;
    END
  END B
  PIN ZN
    DIRECTION OUTPUT ;
    USE SIGNAL ;
    PORT
      LAYER M1 ;
        RECT 0.1900 0.0160 0.2060 0.1040 ;
    END
  END ZN
  OBS
    LAYER M1 DESIGNRULEWIDTH 0 ;
      RECT 0.0580 0.0400 0.0740 0.1040 ;
    LAYER M0 DESIGNRULEWIDTH 0 ;
      RECT 0.1920 0.0200 0.2090 0.0300 ;
      RECT 0.0400 0.0200 0.1800 0.0300 ;
      RECT 0.1480 0.0420 0.2530 0.0540 ;
      RECT 0.0090 0.0420 0.1360 0.0540 ;
      RECT 0.0840 0.0660 0.2250 0.0780 ;
      RECT 0.1440 0.0900 0.2090 0.1000 ;
      RECT 0.0540 0.0900 0.0770 0.1000 ;
  END
END XNOR2_X1

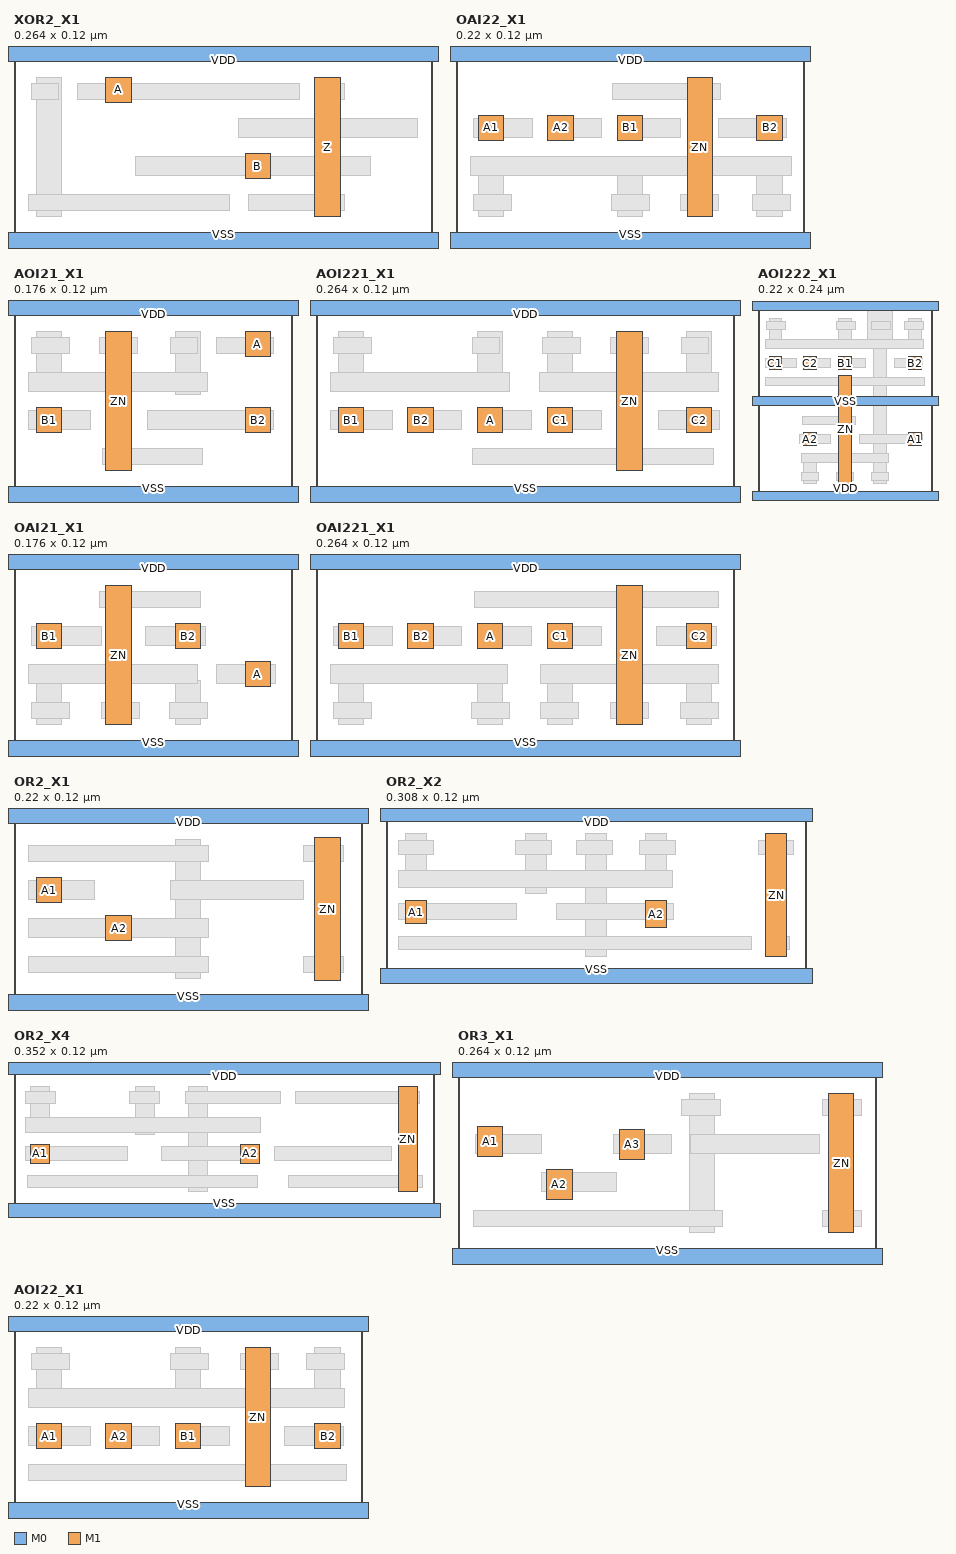
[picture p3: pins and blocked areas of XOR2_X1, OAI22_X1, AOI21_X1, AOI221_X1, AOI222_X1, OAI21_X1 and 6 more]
MACRO XOR2_X1
  CLASS CORE ;
  ORIGIN 0 0 ;
  FOREIGN XOR2_X1 0 0 ;
  SYMMETRY X Y ;
  SITE i3d_nsfet3nm ;
  SIZE 0.264 BY 0.12 ;
  PIN VDD
    DIRECTION INOUT ;
    USE POWER ;
    PORT
      LAYER M0 ;
        RECT -0.0160 0.1140 0.2800 0.1260 ;
    END
  END VDD
  PIN VSS
    DIRECTION INOUT ;
    USE GROUND ;
    PORT
      LAYER M0 ;
        RECT -0.0160 -0.0060 0.2800 0.0060 ;
    END
  END VSS
  PIN A
    DIRECTION INPUT ;
    USE SIGNAL ;
    PORT
      LAYER M1 ;
        RECT 0.0580 0.0880 0.0740 0.1040 ;
    END
  END A
  PIN B
    DIRECTION INPUT ;
    USE SIGNAL ;
    PORT
      LAYER M1 ;
        RECT 0.1460 0.0400 0.1620 0.0560 ;
    END
  END B
  PIN Z
    DIRECTION OUTPUT ;
    USE SIGNAL ;
    PORT
      LAYER M1 ;
        RECT 0.1900 0.0160 0.2060 0.1040 ;
    END
  END Z
  OBS
    LAYER M1 DESIGNRULEWIDTH 0 ;
      RECT 0.0140 0.0160 0.0300 0.1040 ;
    LAYER M0 DESIGNRULEWIDTH 0 ;
      RECT 0.1480 0.0200 0.2090 0.0300 ;
      RECT 0.0090 0.0200 0.1360 0.0300 ;
      RECT 0.0770 0.0420 0.2250 0.0540 ;
      RECT 0.1420 0.0660 0.2550 0.0780 ;
      RECT 0.1920 0.0900 0.2090 0.1000 ;
      RECT 0.0400 0.0900 0.1800 0.1000 ;
      RECT 0.0110 0.0900 0.0280 0.1000 ;
  END
END XOR2_X1

MACRO OAI22_X1
  CLASS CORE ;
  ORIGIN 0 0 ;
  FOREIGN OAI22_X1 0 0 ;
  SYMMETRY X Y ;
  SITE i3d_nsfet3nm ;
  SIZE 0.22 BY 0.12 ;
  PIN VDD
    DIRECTION INOUT ;
    USE POWER ;
    PORT
      LAYER M0 ;
        RECT -0.0160 0.1140 0.2360 0.1260 ;
    END
  END VDD
  PIN A1
    DIRECTION INPUT ;
    USE SIGNAL ;
    PORT
      LAYER M1 ;
        RECT 0.0140 0.0640 0.0300 0.0800 ;
    END
  END A1
  PIN A2
    DIRECTION INPUT ;
    USE SIGNAL ;
    PORT
      LAYER M1 ;
        RECT 0.0580 0.0640 0.0740 0.0800 ;
    END
  END A2
  PIN B1
    DIRECTION INPUT ;
    USE SIGNAL ;
    PORT
      LAYER M1 ;
        RECT 0.1020 0.0640 0.1180 0.0800 ;
    END
  END B1
  PIN ZN
    DIRECTION OUTPUT ;
    USE SIGNAL ;
    PORT
      LAYER M1 ;
        RECT 0.1460 0.0160 0.1620 0.1040 ;
    END
  END ZN
  PIN B2
    DIRECTION INPUT ;
    USE SIGNAL ;
    PORT
      LAYER M1 ;
        RECT 0.1900 0.0640 0.2060 0.0800 ;
    END
  END B2
  PIN VSS
    DIRECTION INOUT ;
    USE GROUND ;
    PORT
      LAYER M0 ;
        RECT -0.0160 -0.0060 0.2360 0.0060 ;
    END
  END VSS
  OBS
    LAYER M1 DESIGNRULEWIDTH 0 ;
      RECT 0.1900 0.0160 0.2060 0.0440 ;
      RECT 0.1020 0.0160 0.1180 0.0440 ;
      RECT 0.0140 0.0160 0.0300 0.0440 ;
    LAYER M0 DESIGNRULEWIDTH 0 ;
      RECT 0.1870 0.0200 0.2110 0.0300 ;
      RECT 0.1420 0.0200 0.1660 0.0300 ;
      RECT 0.0980 0.0200 0.1220 0.0300 ;
      RECT 0.0110 0.0200 0.0350 0.0300 ;
      RECT 0.0090 0.0420 0.2120 0.0540 ;
      RECT 0.1660 0.0660 0.2090 0.0780 ;
      RECT 0.1040 0.0660 0.1420 0.0780 ;
      RECT 0.0600 0.0660 0.0920 0.0780 ;
      RECT 0.0110 0.0660 0.0480 0.0780 ;
      RECT 0.0990 0.0900 0.1670 0.1000 ;
  END
END OAI22_X1

MACRO AOI21_X1
  CLASS CORE ;
  ORIGIN 0 0 ;
  FOREIGN AOI21_X1 0 0 ;
  SYMMETRY X Y ;
  SITE i3d_nsfet3nm ;
  SIZE 0.176 BY 0.12 ;
  PIN VDD
    DIRECTION INOUT ;
    USE POWER ;
    PORT
      LAYER M0 ;
        RECT -0.0160 0.1140 0.1920 0.1260 ;
    END
  END VDD
  PIN B1
    DIRECTION INPUT ;
    USE SIGNAL ;
    PORT
      LAYER M1 ;
        RECT 0.0140 0.0400 0.0300 0.0560 ;
    END
  END B1
  PIN ZN
    DIRECTION OUTPUT ;
    USE SIGNAL ;
    PORT
      LAYER M1 ;
        RECT 0.0580 0.0160 0.0740 0.1040 ;
    END
  END ZN
  PIN A
    DIRECTION INPUT ;
    USE SIGNAL ;
    PORT
      LAYER M1 ;
        RECT 0.1460 0.0880 0.1620 0.1040 ;
    END
  END A
  PIN B2
    DIRECTION INPUT ;
    USE SIGNAL ;
    PORT
      LAYER M1 ;
        RECT 0.1460 0.0400 0.1620 0.0560 ;
    END
  END B2
  PIN VSS
    DIRECTION INOUT ;
    USE GROUND ;
    PORT
      LAYER M0 ;
        RECT -0.0160 -0.0060 0.1920 0.0060 ;
    END
  END VSS
  OBS
    LAYER M1 DESIGNRULEWIDTH 0 ;
      RECT 0.1020 0.0640 0.1180 0.1040 ;
      RECT 0.0140 0.0760 0.0300 0.1040 ;
    LAYER M0 DESIGNRULEWIDTH 0 ;
      RECT 0.0560 0.0200 0.1190 0.0300 ;
      RECT 0.0840 0.0420 0.1640 0.0540 ;
      RECT 0.0090 0.0420 0.0480 0.0540 ;
      RECT 0.0090 0.0660 0.1220 0.0780 ;
      RECT 0.1280 0.0900 0.1640 0.1000 ;
      RECT 0.0990 0.0900 0.1160 0.1000 ;
      RECT 0.0540 0.0900 0.0780 0.1000 ;
      RECT 0.0110 0.0900 0.0350 0.1000 ;
  END
END AOI21_X1

MACRO AOI221_X1
  CLASS CORE ;
  ORIGIN 0 0 ;
  FOREIGN AOI221_X1 0 0 ;
  SYMMETRY X Y ;
  SITE i3d_nsfet3nm ;
  SIZE 0.264 BY 0.12 ;
  PIN VDD
    DIRECTION INOUT ;
    USE POWER ;
    PORT
      LAYER M0 ;
        RECT -0.0160 0.1140 0.2800 0.1260 ;
    END
  END VDD
  PIN VSS
    DIRECTION INOUT ;
    USE GROUND ;
    PORT
      LAYER M0 ;
        RECT -0.0160 -0.0060 0.2800 0.0060 ;
    END
  END VSS
  PIN B1
    DIRECTION INPUT ;
    USE SIGNAL ;
    PORT
      LAYER M1 ;
        RECT 0.0140 0.0400 0.0300 0.0560 ;
    END
  END B1
  PIN B2
    DIRECTION INPUT ;
    USE SIGNAL ;
    PORT
      LAYER M1 ;
        RECT 0.0580 0.0400 0.0740 0.0560 ;
    END
  END B2
  PIN A
    DIRECTION INPUT ;
    USE SIGNAL ;
    PORT
      LAYER M1 ;
        RECT 0.1020 0.0400 0.1180 0.0560 ;
    END
  END A
  PIN C1
    DIRECTION INPUT ;
    USE SIGNAL ;
    PORT
      LAYER M1 ;
        RECT 0.1460 0.0400 0.1620 0.0560 ;
    END
  END C1
  PIN ZN
    DIRECTION OUTPUT ;
    USE SIGNAL ;
    PORT
      LAYER M1 ;
        RECT 0.1900 0.0160 0.2060 0.1040 ;
    END
  END ZN
  PIN C2
    DIRECTION INPUT ;
    USE SIGNAL ;
    PORT
      LAYER M1 ;
        RECT 0.2340 0.0400 0.2500 0.0560 ;
    END
  END C2
  OBS
    LAYER M1 DESIGNRULEWIDTH 0 ;
      RECT 0.2340 0.0760 0.2500 0.1040 ;
      RECT 0.1460 0.0760 0.1620 0.1040 ;
      RECT 0.1020 0.0760 0.1180 0.1040 ;
      RECT 0.0140 0.0760 0.0300 0.1040 ;
    LAYER M0 DESIGNRULEWIDTH 0 ;
      RECT 0.0990 0.0200 0.2510 0.0300 ;
      RECT 0.2160 0.0420 0.2550 0.0540 ;
      RECT 0.1480 0.0420 0.1800 0.0540 ;
      RECT 0.1040 0.0420 0.1360 0.0540 ;
      RECT 0.0600 0.0420 0.0920 0.0540 ;
      RECT 0.0090 0.0420 0.0480 0.0540 ;
      RECT 0.1410 0.0660 0.2540 0.0780 ;
      RECT 0.0090 0.0660 0.1220 0.0780 ;
      RECT 0.2310 0.0900 0.2480 0.1000 ;
      RECT 0.1860 0.0900 0.2100 0.1000 ;
      RECT 0.1430 0.0900 0.1670 0.1000 ;
      RECT 0.0990 0.0900 0.1160 0.1000 ;
      RECT 0.0110 0.0900 0.0350 0.1000 ;
  END
END AOI221_X1

MACRO AOI222_X1
  CLASS CORE ;
  ORIGIN 0 0 ;
  FOREIGN AOI222_X1 0 0 ;
  SYMMETRY X Y ;
  SITE i3d_nsfet3nm_2H_VDD ;
  SIZE 0.22 BY 0.24 ;
  PIN VDD
    DIRECTION INOUT ;
    USE POWER ;
    PORT
      LAYER M0 ;
        RECT -0.0160 -0.0060 0.2360 0.0060 ;
        RECT -0.0160 0.2340 0.2360 0.2460 ;
    END
  END VDD
  PIN VSS
    DIRECTION INOUT ;
    USE GROUND ;
    PORT
      LAYER M0 ;
        RECT -0.0160 0.1140 0.2360 0.1260 ;
    END
  END VSS
  PIN C1
    DIRECTION INPUT ;
    USE SIGNAL ;
    PORT
      LAYER M1 ;
        RECT 0.0140 0.1600 0.0300 0.1760 ;
    END
  END C1
  PIN C2
    DIRECTION INPUT ;
    USE SIGNAL ;
    PORT
      LAYER M1 ;
        RECT 0.0580 0.1600 0.0740 0.1760 ;
    END
  END C2
  PIN B1
    DIRECTION INPUT ;
    USE SIGNAL ;
    PORT
      LAYER M1 ;
        RECT 0.1020 0.1600 0.1180 0.1760 ;
    END
  END B1
  PIN B2
    DIRECTION INPUT ;
    USE SIGNAL ;
    PORT
      LAYER M1 ;
        RECT 0.1900 0.1600 0.2060 0.1760 ;
    END
  END B2
  PIN A2
    DIRECTION INPUT ;
    USE SIGNAL ;
    PORT
      LAYER M1 ;
        RECT 0.0580 0.0640 0.0740 0.0800 ;
    END
  END A2
  PIN A1
    DIRECTION INPUT ;
    USE SIGNAL ;
    PORT
      LAYER M1 ;
        RECT 0.1900 0.0640 0.2060 0.0800 ;
    END
  END A1
  PIN ZN
    DIRECTION OUTPUT ;
    USE SIGNAL ;
    PORT
      LAYER M1 ;
        RECT 0.1020 0.0160 0.1180 0.1520 ;
    END
  END ZN
  OBS
    LAYER M1 DESIGNRULEWIDTH 0 ;
      POLYGON 0.1620 0.0160 0.1620 0.1960 0.1700 0.1960 0.1700 0.2400 0.1380 0.2400 0.1380 0.1960 0.1460 0.1960 0.1460 0.0160 ;
      RECT 0.0580 0.0160 0.0740 0.0440 ;
      RECT 0.1900 0.1960 0.2060 0.2240 ;
      RECT 0.1020 0.1960 0.1180 0.2240 ;
      RECT 0.0140 0.1960 0.0300 0.2240 ;
    LAYER M0 DESIGNRULEWIDTH 0 ;
      RECT 0.1430 0.0200 0.1650 0.0300 ;
      RECT 0.0990 0.0200 0.1210 0.0300 ;
      RECT 0.0550 0.0200 0.0770 0.0300 ;
      RECT 0.0550 0.0420 0.1650 0.0540 ;
      RECT 0.1280 0.0660 0.2080 0.0780 ;
      RECT 0.0530 0.0660 0.0920 0.0780 ;
      RECT 0.0560 0.0900 0.1230 0.1000 ;
      RECT 0.0090 0.1400 0.2100 0.1500 ;
      RECT 0.1720 0.1620 0.2080 0.1740 ;
      RECT 0.1040 0.1620 0.1360 0.1740 ;
      RECT 0.0600 0.1620 0.0920 0.1740 ;
      RECT 0.0090 0.1620 0.0480 0.1740 ;
      RECT 0.0090 0.1860 0.2090 0.1980 ;
      RECT 0.1850 0.2100 0.2090 0.2200 ;
      RECT 0.1430 0.2100 0.1670 0.2200 ;
      RECT 0.0990 0.2100 0.1230 0.2200 ;
      RECT 0.0110 0.2100 0.0350 0.2200 ;
  END
END AOI222_X1

MACRO OAI21_X1
  CLASS CORE ;
  ORIGIN 0 0 ;
  FOREIGN OAI21_X1 0 0 ;
  SYMMETRY X Y ;
  SITE i3d_nsfet3nm ;
  SIZE 0.176 BY 0.12 ;
  PIN VDD
    DIRECTION INOUT ;
    USE POWER ;
    PORT
      LAYER M0 ;
        RECT -0.0160 0.1140 0.1920 0.1260 ;
    END
  END VDD
  PIN VSS
    DIRECTION INOUT ;
    USE GROUND ;
    PORT
      LAYER M0 ;
        RECT -0.0160 -0.0060 0.1920 0.0060 ;
    END
  END VSS
  PIN B1
    DIRECTION INPUT ;
    USE SIGNAL ;
    PORT
      LAYER M1 ;
        RECT 0.0140 0.0640 0.0300 0.0800 ;
    END
  END B1
  PIN ZN
    DIRECTION OUTPUT ;
    USE SIGNAL ;
    PORT
      LAYER M1 ;
        RECT 0.0580 0.0160 0.0740 0.1040 ;
    END
  END ZN
  PIN B2
    DIRECTION INPUT ;
    USE SIGNAL ;
    PORT
      LAYER M1 ;
        RECT 0.1020 0.0640 0.1180 0.0800 ;
    END
  END B2
  PIN A
    DIRECTION INPUT ;
    USE SIGNAL ;
    PORT
      LAYER M1 ;
        RECT 0.1460 0.0400 0.1620 0.0560 ;
    END
  END A
  OBS
    LAYER M1 DESIGNRULEWIDTH 0 ;
      RECT 0.1020 0.0160 0.1180 0.0440 ;
      RECT 0.0140 0.0160 0.0300 0.0440 ;
    LAYER M0 DESIGNRULEWIDTH 0 ;
      RECT 0.0980 0.0200 0.1220 0.0300 ;
      RECT 0.0550 0.0200 0.0790 0.0300 ;
      RECT 0.0110 0.0200 0.0350 0.0300 ;
      RECT 0.1280 0.0420 0.1650 0.0540 ;
      RECT 0.0090 0.0420 0.1160 0.0540 ;
      RECT 0.0830 0.0660 0.1210 0.0780 ;
      RECT 0.0110 0.0660 0.0550 0.0780 ;
      RECT 0.0540 0.0900 0.1180 0.1000 ;
  END
END OAI21_X1

MACRO OAI221_X1
  CLASS CORE ;
  ORIGIN 0 0 ;
  FOREIGN OAI221_X1 0 0 ;
  SYMMETRY X Y ;
  SITE i3d_nsfet3nm ;
  SIZE 0.264 BY 0.12 ;
  PIN VDD
    DIRECTION INOUT ;
    USE POWER ;
    PORT
      LAYER M0 ;
        RECT -0.0160 0.1140 0.2800 0.1260 ;
    END
  END VDD
  PIN VSS
    DIRECTION INOUT ;
    USE GROUND ;
    PORT
      LAYER M0 ;
        RECT -0.0160 -0.0060 0.2800 0.0060 ;
    END
  END VSS
  PIN B1
    DIRECTION INPUT ;
    USE SIGNAL ;
    PORT
      LAYER M1 ;
        RECT 0.0140 0.0640 0.0300 0.0800 ;
    END
  END B1
  PIN B2
    DIRECTION INPUT ;
    USE SIGNAL ;
    PORT
      LAYER M1 ;
        RECT 0.0580 0.0640 0.0740 0.0800 ;
    END
  END B2
  PIN A
    DIRECTION INPUT ;
    USE SIGNAL ;
    PORT
      LAYER M1 ;
        RECT 0.1020 0.0640 0.1180 0.0800 ;
    END
  END A
  PIN C1
    DIRECTION INPUT ;
    USE SIGNAL ;
    PORT
      LAYER M1 ;
        RECT 0.1460 0.0640 0.1620 0.0800 ;
    END
  END C1
  PIN ZN
    DIRECTION OUTPUT ;
    USE SIGNAL ;
    PORT
      LAYER M1 ;
        RECT 0.1900 0.0160 0.2060 0.1040 ;
    END
  END ZN
  PIN C2
    DIRECTION INPUT ;
    USE SIGNAL ;
    PORT
      LAYER M1 ;
        RECT 0.2340 0.0640 0.2500 0.0800 ;
    END
  END C2
  OBS
    LAYER M1 DESIGNRULEWIDTH 0 ;
      RECT 0.2340 0.0160 0.2500 0.0440 ;
      RECT 0.1460 0.0160 0.1620 0.0440 ;
      RECT 0.1020 0.0160 0.1180 0.0440 ;
      RECT 0.0140 0.0160 0.0300 0.0440 ;
    LAYER M0 DESIGNRULEWIDTH 0 ;
      RECT 0.2300 0.0200 0.2540 0.0300 ;
      RECT 0.1860 0.0200 0.2100 0.0300 ;
      RECT 0.1420 0.0200 0.1660 0.0300 ;
      RECT 0.0980 0.0200 0.1220 0.0300 ;
      RECT 0.0110 0.0200 0.0350 0.0300 ;
      RECT 0.1420 0.0420 0.2540 0.0540 ;
      RECT 0.0090 0.0420 0.1210 0.0540 ;
      RECT 0.2150 0.0660 0.2530 0.0780 ;
      RECT 0.1480 0.0660 0.1800 0.0780 ;
      RECT 0.1040 0.0660 0.1360 0.0780 ;
      RECT 0.0600 0.0660 0.0920 0.0780 ;
      RECT 0.0110 0.0660 0.0480 0.0780 ;
      RECT 0.1000 0.0900 0.2540 0.1000 ;
  END
END OAI221_X1

MACRO OR2_X1
  CLASS CORE ;
  ORIGIN 0 0 ;
  FOREIGN OR2_X1 0 0 ;
  SYMMETRY X Y ;
  SITE i3d_nsfet3nm ;
  SIZE 0.22 BY 0.12 ;
  PIN VDD
    DIRECTION INOUT ;
    USE POWER ;
    PORT
      LAYER M0 ;
        RECT -0.0160 0.1140 0.2360 0.1260 ;
    END
  END VDD
  PIN VSS
    DIRECTION INOUT ;
    USE GROUND ;
    PORT
      LAYER M0 ;
        RECT -0.0160 -0.0060 0.2360 0.0060 ;
    END
  END VSS
  PIN A1
    DIRECTION INPUT ;
    USE SIGNAL ;
    PORT
      LAYER M1 ;
        RECT 0.0140 0.0640 0.0300 0.0800 ;
    END
  END A1
  PIN ZN
    DIRECTION OUTPUT ;
    USE SIGNAL ;
    PORT
      LAYER M1 ;
        RECT 0.1900 0.0150 0.2060 0.1050 ;
    END
  END ZN
  PIN A2
    DIRECTION INPUT ;
    USE SIGNAL ;
    PORT
      LAYER M1 ;
        RECT 0.0580 0.0400 0.0740 0.0560 ;
    END
  END A2
  OBS
    LAYER M1 DESIGNRULEWIDTH 0 ;
      RECT 0.1020 0.0160 0.1180 0.1040 ;
    LAYER M0 DESIGNRULEWIDTH 0 ;
      RECT 0.1830 0.0200 0.2080 0.0300 ;
      RECT 0.0090 0.0200 0.1230 0.0300 ;
      RECT 0.0090 0.0420 0.1230 0.0540 ;
      RECT 0.0990 0.0660 0.1830 0.0780 ;
      RECT 0.0090 0.0660 0.0510 0.0780 ;
      RECT 0.1830 0.0900 0.2080 0.1000 ;
      RECT 0.0090 0.0900 0.1230 0.1000 ;
  END
END OR2_X1

MACRO OR2_X2
  CLASS CORE ;
  ORIGIN 0 0 ;
  FOREIGN OR2_X2 0 0 ;
  SYMMETRY X Y ;
  SITE i3d_nsfet3nm ;
  SIZE 0.308 BY 0.12 ;
  PIN VDD
    DIRECTION INOUT ;
    USE POWER ;
    PORT
      LAYER M0 ;
        RECT -0.0160 0.1140 0.3240 0.1260 ;
    END
  END VDD
  PIN VSS
    DIRECTION INOUT ;
    USE GROUND ;
    PORT
      LAYER M0 ;
        RECT -0.0160 -0.0060 0.3240 0.0060 ;
    END
  END VSS
  PIN A1
    DIRECTION INPUT ;
    USE SIGNAL ;
    PORT
      LAYER M1 ;
        RECT 0.0140 0.0390 0.0300 0.0560 ;
    END
  END A1
  PIN A2
    DIRECTION INPUT ;
    USE SIGNAL ;
    PORT
      LAYER M1 ;
        RECT 0.1900 0.0360 0.2060 0.0560 ;
    END
  END A2
  PIN ZN
    DIRECTION OUTPUT ;
    USE SIGNAL ;
    PORT
      LAYER M1 ;
        RECT 0.2780 0.0150 0.2940 0.1050 ;
    END
  END ZN
  OBS
    LAYER M1 DESIGNRULEWIDTH 0 ;
      RECT 0.1460 0.0150 0.1620 0.1050 ;
      RECT 0.1020 0.0610 0.1180 0.1050 ;
      RECT 0.1900 0.0760 0.2060 0.1050 ;
      RECT 0.0140 0.0760 0.0300 0.1050 ;
    LAYER M0 DESIGNRULEWIDTH 0 ;
      RECT 0.2800 0.0200 0.2960 0.0300 ;
      RECT 0.0090 0.0200 0.2680 0.0300 ;
      RECT 0.1250 0.0420 0.2110 0.0540 ;
      RECT 0.0090 0.0420 0.0960 0.0540 ;
      RECT 0.0090 0.0660 0.2100 0.0780 ;
      RECT 0.2730 0.0900 0.2990 0.1000 ;
      RECT 0.1860 0.0900 0.2120 0.1000 ;
      RECT 0.1400 0.0900 0.1660 0.1000 ;
      RECT 0.0950 0.0900 0.1210 0.1000 ;
      RECT 0.0090 0.0900 0.0350 0.1000 ;
  END
END OR2_X2

MACRO OR2_X4
  CLASS CORE ;
  ORIGIN 0 0 ;
  FOREIGN OR2_X4 0 0 ;
  SYMMETRY X Y ;
  SITE i3d_nsfet3nm ;
  SIZE 0.352 BY 0.12 ;
  PIN VDD
    DIRECTION INOUT ;
    USE POWER ;
    PORT
      LAYER M0 ;
        RECT -0.0160 0.1140 0.3680 0.1260 ;
    END
  END VDD
  PIN VSS
    DIRECTION INOUT ;
    USE GROUND ;
    PORT
      LAYER M0 ;
        RECT -0.0160 -0.0060 0.3680 0.0060 ;
    END
  END VSS
  PIN A1
    DIRECTION INPUT ;
    USE SIGNAL ;
    PORT
      LAYER M1 ;
        RECT 0.0140 0.0400 0.0300 0.0560 ;
    END
  END A1
  PIN A2
    DIRECTION INPUT ;
    USE SIGNAL ;
    PORT
      LAYER M1 ;
        RECT 0.1900 0.0400 0.2060 0.0560 ;
    END
  END A2
  PIN ZN
    DIRECTION OUTPUT ;
    USE SIGNAL ;
    PORT
      LAYER M1 ;
        RECT 0.3220 0.0160 0.3380 0.1040 ;
    END
  END ZN
  OBS
    LAYER M1 DESIGNRULEWIDTH 0 ;
      RECT 0.1460 0.0160 0.1620 0.1040 ;
      RECT 0.1020 0.0640 0.1180 0.1040 ;
      RECT 0.0140 0.0760 0.0300 0.1040 ;
    LAYER M0 DESIGNRULEWIDTH 0 ;
      RECT 0.2300 0.0200 0.3420 0.0300 ;
      RECT 0.0110 0.0200 0.2040 0.0300 ;
      RECT 0.2180 0.0420 0.3160 0.0540 ;
      RECT 0.1240 0.0420 0.2050 0.0540 ;
      RECT 0.0100 0.0420 0.0950 0.0540 ;
      RECT 0.0100 0.0660 0.2070 0.0780 ;
      RECT 0.2360 0.0900 0.3400 0.1000 ;
      RECT 0.1440 0.0900 0.2230 0.1000 ;
      RECT 0.0970 0.0900 0.1220 0.1000 ;
      RECT 0.0100 0.0900 0.0350 0.1000 ;
  END
END OR2_X4

MACRO OR3_X1
  CLASS CORE ;
  ORIGIN 0 0 ;
  FOREIGN OR3_X1 0 0 ;
  SYMMETRY X Y ;
  SITE i3d_nsfet3nm ;
  SIZE 0.264 BY 0.12 ;
  PIN VDD
    DIRECTION INOUT ;
    USE POWER ;
    PORT
      LAYER M0 ;
        RECT -0.0160 0.1140 0.2800 0.1260 ;
    END
  END VDD
  PIN VSS
    DIRECTION INOUT ;
    USE GROUND ;
    PORT
      LAYER M0 ;
        RECT -0.0160 -0.0060 0.2800 0.0060 ;
    END
  END VSS
  PIN A1
    DIRECTION INPUT ;
    USE SIGNAL ;
    PORT
      LAYER M1 ;
        RECT 0.0120 0.0640 0.0280 0.0830 ;
    END
  END A1
  PIN A2
    DIRECTION INPUT ;
    USE SIGNAL ;
    PORT
      LAYER M1 ;
        RECT 0.0560 0.0370 0.0720 0.0560 ;
    END
  END A2
  PIN A3
    DIRECTION INPUT ;
    USE SIGNAL ;
    PORT
      LAYER M1 ;
        RECT 0.1020 0.0620 0.1180 0.0810 ;
    END
  END A3
  PIN ZN
    DIRECTION OUTPUT ;
    USE SIGNAL ;
    PORT
      LAYER M1 ;
        RECT 0.2340 0.0160 0.2500 0.1040 ;
    END
  END ZN
  OBS
    LAYER M1 DESIGNRULEWIDTH 0 ;
      RECT 0.1460 0.0160 0.1620 0.1040 ;
    LAYER M0 DESIGNRULEWIDTH 0 ;
      RECT 0.2300 0.0200 0.2550 0.0300 ;
      RECT 0.0100 0.0200 0.1670 0.0300 ;
      RECT 0.0530 0.0420 0.1000 0.0540 ;
      RECT 0.1470 0.0660 0.2280 0.0780 ;
      RECT 0.0980 0.0660 0.1350 0.0780 ;
      RECT 0.0110 0.0660 0.0530 0.0780 ;
      RECT 0.2300 0.0900 0.2550 0.1000 ;
      RECT 0.1410 0.0900 0.1660 0.1000 ;
  END
END OR3_X1

MACRO AOI22_X1
  CLASS CORE ;
  ORIGIN 0 0 ;
  FOREIGN AOI22_X1 0 0 ;
  SYMMETRY X Y ;
  SITE i3d_nsfet3nm ;
  SIZE 0.22 BY 0.12 ;
  PIN VDD
    DIRECTION INOUT ;
    USE POWER ;
    PORT
      LAYER M0 ;
        RECT -0.0160 0.1140 0.2360 0.1260 ;
    END
  END VDD
  PIN VSS
    DIRECTION INOUT ;
    USE GROUND ;
    PORT
      LAYER M0 ;
        RECT -0.0160 -0.0060 0.2360 0.0060 ;
    END
  END VSS
  PIN A1
    DIRECTION INPUT ;
    USE SIGNAL ;
    PORT
      LAYER M1 ;
        RECT 0.0140 0.0400 0.0300 0.0560 ;
    END
  END A1
  PIN A2
    DIRECTION INPUT ;
    USE SIGNAL ;
    PORT
      LAYER M1 ;
        RECT 0.0580 0.0400 0.0740 0.0560 ;
    END
  END A2
  PIN B1
    DIRECTION INPUT ;
    USE SIGNAL ;
    PORT
      LAYER M1 ;
        RECT 0.1020 0.0400 0.1180 0.0560 ;
    END
  END B1
  PIN ZN
    DIRECTION OUTPUT ;
    USE SIGNAL ;
    PORT
      LAYER M1 ;
        RECT 0.1460 0.0160 0.1620 0.1040 ;
    END
  END ZN
  PIN B2
    DIRECTION INPUT ;
    USE SIGNAL ;
    PORT
      LAYER M1 ;
        RECT 0.1900 0.0400 0.2060 0.0560 ;
    END
  END B2
  OBS
    LAYER M1 DESIGNRULEWIDTH 0 ;
      RECT 0.1900 0.0760 0.2060 0.1040 ;
      RECT 0.1020 0.0760 0.1180 0.1040 ;
      RECT 0.0140 0.0760 0.0300 0.1040 ;
    LAYER M0 DESIGNRULEWIDTH 0 ;
      RECT 0.0090 0.0200 0.2100 0.0300 ;
      RECT 0.1710 0.0420 0.2080 0.0540 ;
      RECT 0.1040 0.0420 0.1360 0.0540 ;
      RECT 0.0600 0.0420 0.0920 0.0540 ;
      RECT 0.0090 0.0420 0.0480 0.0540 ;
      RECT 0.0090 0.0660 0.2090 0.0780 ;
      RECT 0.1850 0.0900 0.2090 0.1000 ;
      RECT 0.1430 0.0900 0.1670 0.1000 ;
      RECT 0.0990 0.0900 0.1230 0.1000 ;
      RECT 0.0110 0.0900 0.0350 0.1000 ;
  END
END AOI22_X1

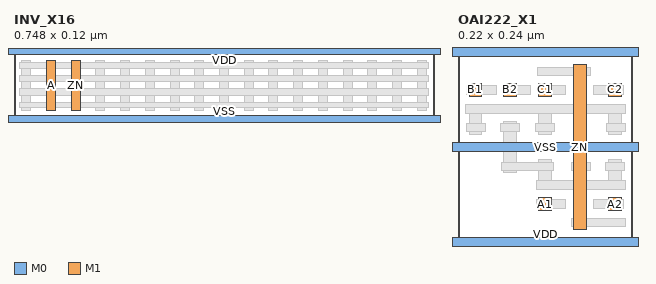
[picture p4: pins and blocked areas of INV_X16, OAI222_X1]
MACRO INV_X16
  CLASS CORE ;
  ORIGIN 0 0 ;
  FOREIGN INV_X16 0 0 ;
  SYMMETRY X Y ;
  SITE i3d_nsfet3nm ;
  SIZE 0.748 BY 0.12 ;
  PIN VDD
    DIRECTION INOUT ;
    USE POWER ;
    PORT
      LAYER M0 ;
        RECT -0.0160 0.1140 0.7640 0.1260 ;
    END
  END VDD
  PIN VSS
    DIRECTION INOUT ;
    USE GROUND ;
    PORT
      LAYER M0 ;
        RECT -0.0160 -0.0060 0.7640 0.0060 ;
    END
  END VSS
  PIN A
    DIRECTION INPUT ;
    USE SIGNAL ;
    PORT
      LAYER M1 ;
        RECT 0.0580 0.0160 0.0740 0.1040 ;
    END
  END A
  PIN ZN
    DIRECTION OUTPUT ;
    USE SIGNAL ;
    PORT
      LAYER M1 ;
        RECT 0.1020 0.0160 0.1180 0.1040 ;
    END
  END ZN
  OBS
    LAYER M1 DESIGNRULEWIDTH 0 ;
      RECT 0.7180 0.0160 0.7340 0.1040 ;
      RECT 0.6740 0.0160 0.6900 0.1040 ;
      RECT 0.6300 0.0160 0.6460 0.1040 ;
      RECT 0.5860 0.0160 0.6020 0.1040 ;
      RECT 0.5420 0.0160 0.5580 0.1040 ;
      RECT 0.4980 0.0160 0.5140 0.1040 ;
      RECT 0.4540 0.0160 0.4700 0.1040 ;
      RECT 0.4100 0.0160 0.4260 0.1040 ;
      RECT 0.3660 0.0160 0.3820 0.1040 ;
      RECT 0.3220 0.0160 0.3380 0.1040 ;
      RECT 0.2780 0.0160 0.2940 0.1040 ;
      RECT 0.2340 0.0160 0.2500 0.1040 ;
      RECT 0.1900 0.0160 0.2060 0.1040 ;
      RECT 0.1460 0.0160 0.1620 0.1040 ;
      RECT 0.0140 0.0160 0.0300 0.1040 ;
    LAYER M0 DESIGNRULEWIDTH 0 ;
      RECT 0.0090 0.0200 0.7380 0.0300 ;
      RECT 0.0090 0.0420 0.7380 0.0540 ;
      RECT 0.0090 0.0660 0.7380 0.0780 ;
      RECT 0.0090 0.0900 0.7380 0.1000 ;
  END
END INV_X16

MACRO OAI222_X1
  CLASS CORE ;
  ORIGIN 0 0 ;
  FOREIGN OAI222_X1 0 0 ;
  SYMMETRY X Y ;
  SITE i3d_nsfet3nm_2H_VDD ;
  SIZE 0.22 BY 0.24 ;
  PIN VDD
    DIRECTION INOUT ;
    USE POWER ;
    PORT
      LAYER M0 ;
        RECT -0.0160 -0.0060 0.2360 0.0060 ;
        RECT -0.0160 0.2340 0.2360 0.2460 ;
    END
  END VDD
  PIN VSS
    DIRECTION INOUT ;
    USE GROUND ;
    PORT
      LAYER M0 ;
        RECT -0.0160 0.1140 0.2360 0.1260 ;
    END
  END VSS
  PIN B1
    DIRECTION INPUT ;
    USE SIGNAL ;
    PORT
      LAYER M1 ;
        RECT 0.0140 0.1840 0.0300 0.2000 ;
    END
  END B1
  PIN B2
    DIRECTION INPUT ;
    USE SIGNAL ;
    PORT
      LAYER M1 ;
        RECT 0.0580 0.1840 0.0740 0.2000 ;
    END
  END B2
  PIN C1
    DIRECTION INPUT ;
    USE SIGNAL ;
    PORT
      LAYER M1 ;
        RECT 0.1020 0.1840 0.1180 0.2000 ;
    END
  END C1
  PIN ZN
    DIRECTION OUTPUT ;
    USE SIGNAL ;
    PORT
      LAYER M1 ;
        RECT 0.1460 0.0160 0.1620 0.2240 ;
    END
  END ZN
  PIN C2
    DIRECTION INPUT ;
    USE SIGNAL ;
    PORT
      LAYER M1 ;
        RECT 0.1900 0.1840 0.2060 0.2000 ;
    END
  END C2
  PIN A1
    DIRECTION INPUT ;
    USE SIGNAL ;
    PORT
      LAYER M1 ;
        RECT 0.1020 0.0400 0.1180 0.0560 ;
    END
  END A1
  PIN A2
    DIRECTION INPUT ;
    USE SIGNAL ;
    PORT
      LAYER M1 ;
        RECT 0.1900 0.0400 0.2060 0.0560 ;
    END
  END A2
  OBS
    LAYER M1 DESIGNRULEWIDTH 0 ;
      RECT 0.1900 0.0760 0.2060 0.1040 ;
      RECT 0.1020 0.0760 0.1180 0.1040 ;
      RECT 0.0580 0.0880 0.0740 0.1520 ;
      RECT 0.1900 0.1360 0.2060 0.1640 ;
      RECT 0.1020 0.1360 0.1180 0.1640 ;
      RECT 0.0140 0.1360 0.0300 0.1640 ;
    LAYER M0 DESIGNRULEWIDTH 0 ;
      RECT 0.1430 0.0200 0.2110 0.0300 ;
      RECT 0.1710 0.0420 0.2090 0.0540 ;
      RECT 0.0990 0.0420 0.1360 0.0540 ;
      RECT 0.0990 0.0660 0.2120 0.0780 ;
      RECT 0.1860 0.0900 0.2100 0.1000 ;
      RECT 0.1430 0.0900 0.1670 0.1000 ;
      RECT 0.0550 0.0900 0.1210 0.1000 ;
      RECT 0.1870 0.1400 0.2110 0.1500 ;
      RECT 0.0980 0.1400 0.1220 0.1500 ;
      RECT 0.0540 0.1400 0.0780 0.1500 ;
      RECT 0.0110 0.1400 0.0350 0.1500 ;
      RECT 0.0090 0.1620 0.2120 0.1740 ;
      RECT 0.1710 0.1860 0.2090 0.1980 ;
      RECT 0.1040 0.1860 0.1360 0.1980 ;
      RECT 0.0600 0.1860 0.0920 0.1980 ;
      RECT 0.0110 0.1860 0.0480 0.1980 ;
      RECT 0.1010 0.2100 0.1670 0.2200 ;
  END
END OAI222_X1

END LIBRARY
